VERSION 5.8 ;
BUSBITCHARS "[]" ;
DIVIDERCHAR "/" ;
UNITS
    DATABASE MICRONS 1000 ;
END UNITS

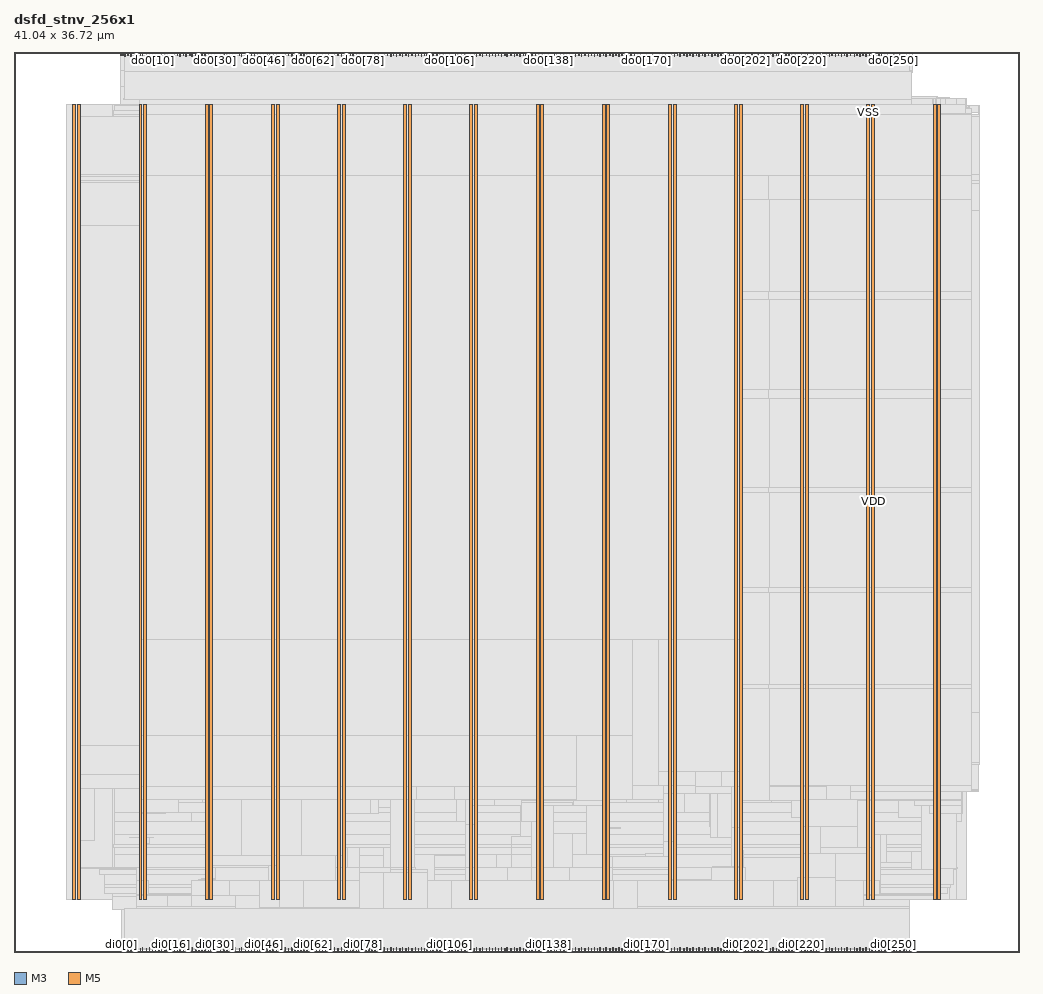
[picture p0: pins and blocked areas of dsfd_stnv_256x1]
MACRO dsfd_stnv_256x1
  FOREIGN dsfd_stnv_256x1 0 0 ;
  CLASS BLOCK ;
  SIZE 41.04 BY 36.72 ;
  PIN di0[0]
    DIRECTION INPUT ;
    USE SIGNAL ;
    PORT
      LAYER M3 ;
        RECT  4.392 0 4.41 0.144 ;
    END
  END di0[0]
  PIN di0[100]
    DIRECTION INPUT ;
    USE SIGNAL ;
    PORT
      LAYER M3 ;
        RECT  16.992 0 17.01 0.144 ;
    END
  END di0[100]
  PIN di0[101]
    DIRECTION INPUT ;
    USE SIGNAL ;
    PORT
      LAYER M5 ;
        RECT  17.088 0 17.112 0.192 ;
    END
  END di0[101]
  PIN di0[102]
    DIRECTION INPUT ;
    USE SIGNAL ;
    PORT
      LAYER M3 ;
        RECT  17.244 0 17.262 0.144 ;
    END
  END di0[102]
  PIN di0[103]
    DIRECTION INPUT ;
    USE SIGNAL ;
    PORT
      LAYER M5 ;
        RECT  17.376 0 17.4 0.192 ;
    END
  END di0[103]
  PIN di0[104]
    DIRECTION INPUT ;
    USE SIGNAL ;
    PORT
      LAYER M3 ;
        RECT  17.496 0 17.514 0.144 ;
    END
  END di0[104]
  PIN di0[105]
    DIRECTION INPUT ;
    USE SIGNAL ;
    PORT
      LAYER M5 ;
        RECT  17.616 0 17.64 0.192 ;
    END
  END di0[105]
  PIN di0[106]
    DIRECTION INPUT ;
    USE SIGNAL ;
    PORT
      LAYER M3 ;
        RECT  17.748 0 17.766 0.144 ;
    END
  END di0[106]
  PIN di0[107]
    DIRECTION INPUT ;
    USE SIGNAL ;
    PORT
      LAYER M5 ;
        RECT  17.856 0 17.88 0.192 ;
    END
  END di0[107]
  PIN di0[108]
    DIRECTION INPUT ;
    USE SIGNAL ;
    PORT
      LAYER M3 ;
        RECT  18 0 18.018 0.144 ;
    END
  END di0[108]
  PIN di0[109]
    DIRECTION INPUT ;
    USE SIGNAL ;
    PORT
      LAYER M5 ;
        RECT  18.096 0 18.12 0.192 ;
    END
  END di0[109]
  PIN di0[10]
    DIRECTION INPUT ;
    USE SIGNAL ;
    PORT
      LAYER M3 ;
        RECT  5.652 0 5.67 0.144 ;
    END
  END di0[10]
  PIN di0[110]
    DIRECTION INPUT ;
    USE SIGNAL ;
    PORT
      LAYER M3 ;
        RECT  18.252 0 18.27 0.144 ;
    END
  END di0[110]
  PIN di0[111]
    DIRECTION INPUT ;
    USE SIGNAL ;
    PORT
      LAYER M5 ;
        RECT  18.384 0 18.408 0.192 ;
    END
  END di0[111]
  PIN di0[112]
    DIRECTION INPUT ;
    USE SIGNAL ;
    PORT
      LAYER M3 ;
        RECT  18.504 0 18.522 0.144 ;
    END
  END di0[112]
  PIN di0[113]
    DIRECTION INPUT ;
    USE SIGNAL ;
    PORT
      LAYER M5 ;
        RECT  18.624 0 18.648 0.192 ;
    END
  END di0[113]
  PIN di0[114]
    DIRECTION INPUT ;
    USE SIGNAL ;
    PORT
      LAYER M3 ;
        RECT  18.756 0 18.774 0.144 ;
    END
  END di0[114]
  PIN di0[115]
    DIRECTION INPUT ;
    USE SIGNAL ;
    PORT
      LAYER M5 ;
        RECT  18.864 0 18.888 0.192 ;
    END
  END di0[115]
  PIN di0[116]
    DIRECTION INPUT ;
    USE SIGNAL ;
    PORT
      LAYER M3 ;
        RECT  19.008 0 19.026 0.144 ;
    END
  END di0[116]
  PIN di0[117]
    DIRECTION INPUT ;
    USE SIGNAL ;
    PORT
      LAYER M5 ;
        RECT  19.104 0 19.128 0.192 ;
    END
  END di0[117]
  PIN di0[118]
    DIRECTION INPUT ;
    USE SIGNAL ;
    PORT
      LAYER M3 ;
        RECT  19.26 0 19.278 0.144 ;
    END
  END di0[118]
  PIN di0[119]
    DIRECTION INPUT ;
    USE SIGNAL ;
    PORT
      LAYER M5 ;
        RECT  19.392 0 19.416 0.192 ;
    END
  END di0[119]
  PIN di0[11]
    DIRECTION INPUT ;
    USE SIGNAL ;
    PORT
      LAYER M5 ;
        RECT  5.76 0 5.784 0.192 ;
    END
  END di0[11]
  PIN di0[120]
    DIRECTION INPUT ;
    USE SIGNAL ;
    PORT
      LAYER M3 ;
        RECT  19.512 0 19.53 0.144 ;
    END
  END di0[120]
  PIN di0[121]
    DIRECTION INPUT ;
    USE SIGNAL ;
    PORT
      LAYER M5 ;
        RECT  19.632 0 19.656 0.192 ;
    END
  END di0[121]
  PIN di0[122]
    DIRECTION INPUT ;
    USE SIGNAL ;
    PORT
      LAYER M3 ;
        RECT  19.764 0 19.782 0.144 ;
    END
  END di0[122]
  PIN di0[123]
    DIRECTION INPUT ;
    USE SIGNAL ;
    PORT
      LAYER M5 ;
        RECT  19.872 0 19.896 0.192 ;
    END
  END di0[123]
  PIN di0[124]
    DIRECTION INPUT ;
    USE SIGNAL ;
    PORT
      LAYER M3 ;
        RECT  20.016 0 20.034 0.144 ;
    END
  END di0[124]
  PIN di0[125]
    DIRECTION INPUT ;
    USE SIGNAL ;
    PORT
      LAYER M5 ;
        RECT  20.112 0 20.136 0.192 ;
    END
  END di0[125]
  PIN di0[126]
    DIRECTION INPUT ;
    USE SIGNAL ;
    PORT
      LAYER M3 ;
        RECT  20.268 0 20.286 0.144 ;
    END
  END di0[126]
  PIN di0[127]
    DIRECTION INPUT ;
    USE SIGNAL ;
    PORT
      LAYER M5 ;
        RECT  20.4 0 20.424 0.192 ;
    END
  END di0[127]
  PIN di0[128]
    DIRECTION INPUT ;
    USE SIGNAL ;
    PORT
      LAYER M3 ;
        RECT  20.52 0 20.538 0.144 ;
    END
  END di0[128]
  PIN di0[129]
    DIRECTION INPUT ;
    USE SIGNAL ;
    PORT
      LAYER M5 ;
        RECT  20.64 0 20.664 0.192 ;
    END
  END di0[129]
  PIN di0[12]
    DIRECTION INPUT ;
    USE SIGNAL ;
    PORT
      LAYER M3 ;
        RECT  5.904 0 5.922 0.144 ;
    END
  END di0[12]
  PIN di0[130]
    DIRECTION INPUT ;
    USE SIGNAL ;
    PORT
      LAYER M3 ;
        RECT  20.772 0 20.79 0.144 ;
    END
  END di0[130]
  PIN di0[131]
    DIRECTION INPUT ;
    USE SIGNAL ;
    PORT
      LAYER M5 ;
        RECT  20.88 0 20.904 0.192 ;
    END
  END di0[131]
  PIN di0[132]
    DIRECTION INPUT ;
    USE SIGNAL ;
    PORT
      LAYER M3 ;
        RECT  21.024 0 21.042 0.144 ;
    END
  END di0[132]
  PIN di0[133]
    DIRECTION INPUT ;
    USE SIGNAL ;
    PORT
      LAYER M5 ;
        RECT  21.12 0 21.144 0.192 ;
    END
  END di0[133]
  PIN di0[134]
    DIRECTION INPUT ;
    USE SIGNAL ;
    PORT
      LAYER M3 ;
        RECT  21.276 0 21.294 0.144 ;
    END
  END di0[134]
  PIN di0[135]
    DIRECTION INPUT ;
    USE SIGNAL ;
    PORT
      LAYER M5 ;
        RECT  21.408 0 21.432 0.192 ;
    END
  END di0[135]
  PIN di0[136]
    DIRECTION INPUT ;
    USE SIGNAL ;
    PORT
      LAYER M3 ;
        RECT  21.528 0 21.546 0.144 ;
    END
  END di0[136]
  PIN di0[137]
    DIRECTION INPUT ;
    USE SIGNAL ;
    PORT
      LAYER M5 ;
        RECT  21.648 0 21.672 0.192 ;
    END
  END di0[137]
  PIN di0[138]
    DIRECTION INPUT ;
    USE SIGNAL ;
    PORT
      LAYER M3 ;
        RECT  21.78 0 21.798 0.144 ;
    END
  END di0[138]
  PIN di0[139]
    DIRECTION INPUT ;
    USE SIGNAL ;
    PORT
      LAYER M5 ;
        RECT  21.888 0 21.912 0.192 ;
    END
  END di0[139]
  PIN di0[13]
    DIRECTION INPUT ;
    USE SIGNAL ;
    PORT
      LAYER M5 ;
        RECT  6 0 6.024 0.192 ;
    END
  END di0[13]
  PIN di0[140]
    DIRECTION INPUT ;
    USE SIGNAL ;
    PORT
      LAYER M3 ;
        RECT  22.032 0 22.05 0.144 ;
    END
  END di0[140]
  PIN di0[141]
    DIRECTION INPUT ;
    USE SIGNAL ;
    PORT
      LAYER M5 ;
        RECT  22.128 0 22.152 0.192 ;
    END
  END di0[141]
  PIN di0[142]
    DIRECTION INPUT ;
    USE SIGNAL ;
    PORT
      LAYER M3 ;
        RECT  22.284 0 22.302 0.144 ;
    END
  END di0[142]
  PIN di0[143]
    DIRECTION INPUT ;
    USE SIGNAL ;
    PORT
      LAYER M5 ;
        RECT  22.416 0 22.44 0.192 ;
    END
  END di0[143]
  PIN di0[144]
    DIRECTION INPUT ;
    USE SIGNAL ;
    PORT
      LAYER M3 ;
        RECT  22.536 0 22.554 0.144 ;
    END
  END di0[144]
  PIN di0[145]
    DIRECTION INPUT ;
    USE SIGNAL ;
    PORT
      LAYER M5 ;
        RECT  22.656 0 22.68 0.192 ;
    END
  END di0[145]
  PIN di0[146]
    DIRECTION INPUT ;
    USE SIGNAL ;
    PORT
      LAYER M3 ;
        RECT  22.788 0 22.806 0.144 ;
    END
  END di0[146]
  PIN di0[147]
    DIRECTION INPUT ;
    USE SIGNAL ;
    PORT
      LAYER M5 ;
        RECT  22.896 0 22.92 0.192 ;
    END
  END di0[147]
  PIN di0[148]
    DIRECTION INPUT ;
    USE SIGNAL ;
    PORT
      LAYER M3 ;
        RECT  23.04 0 23.058 0.144 ;
    END
  END di0[148]
  PIN di0[149]
    DIRECTION INPUT ;
    USE SIGNAL ;
    PORT
      LAYER M5 ;
        RECT  23.136 0 23.16 0.192 ;
    END
  END di0[149]
  PIN di0[14]
    DIRECTION INPUT ;
    USE SIGNAL ;
    PORT
      LAYER M3 ;
        RECT  6.156 0 6.174 0.144 ;
    END
  END di0[14]
  PIN di0[150]
    DIRECTION INPUT ;
    USE SIGNAL ;
    PORT
      LAYER M3 ;
        RECT  23.292 0 23.31 0.144 ;
    END
  END di0[150]
  PIN di0[151]
    DIRECTION INPUT ;
    USE SIGNAL ;
    PORT
      LAYER M5 ;
        RECT  23.424 0 23.448 0.192 ;
    END
  END di0[151]
  PIN di0[152]
    DIRECTION INPUT ;
    USE SIGNAL ;
    PORT
      LAYER M3 ;
        RECT  23.544 0 23.562 0.144 ;
    END
  END di0[152]
  PIN di0[153]
    DIRECTION INPUT ;
    USE SIGNAL ;
    PORT
      LAYER M5 ;
        RECT  23.664 0 23.688 0.192 ;
    END
  END di0[153]
  PIN di0[154]
    DIRECTION INPUT ;
    USE SIGNAL ;
    PORT
      LAYER M3 ;
        RECT  23.796 0 23.814 0.144 ;
    END
  END di0[154]
  PIN di0[155]
    DIRECTION INPUT ;
    USE SIGNAL ;
    PORT
      LAYER M5 ;
        RECT  23.904 0 23.928 0.192 ;
    END
  END di0[155]
  PIN di0[156]
    DIRECTION INPUT ;
    USE SIGNAL ;
    PORT
      LAYER M3 ;
        RECT  24.048 0 24.066 0.144 ;
    END
  END di0[156]
  PIN di0[157]
    DIRECTION INPUT ;
    USE SIGNAL ;
    PORT
      LAYER M5 ;
        RECT  24.144 0 24.168 0.192 ;
    END
  END di0[157]
  PIN di0[158]
    DIRECTION INPUT ;
    USE SIGNAL ;
    PORT
      LAYER M3 ;
        RECT  24.3 0 24.318 0.144 ;
    END
  END di0[158]
  PIN di0[159]
    DIRECTION INPUT ;
    USE SIGNAL ;
    PORT
      LAYER M5 ;
        RECT  24.432 0 24.456 0.192 ;
    END
  END di0[159]
  PIN di0[15]
    DIRECTION INPUT ;
    USE SIGNAL ;
    PORT
      LAYER M5 ;
        RECT  6.24 0 6.264 0.192 ;
    END
  END di0[15]
  PIN di0[160]
    DIRECTION INPUT ;
    USE SIGNAL ;
    PORT
      LAYER M3 ;
        RECT  24.552 0 24.57 0.144 ;
    END
  END di0[160]
  PIN di0[161]
    DIRECTION INPUT ;
    USE SIGNAL ;
    PORT
      LAYER M5 ;
        RECT  24.672 0 24.696 0.192 ;
    END
  END di0[161]
  PIN di0[162]
    DIRECTION INPUT ;
    USE SIGNAL ;
    PORT
      LAYER M3 ;
        RECT  24.804 0 24.822 0.144 ;
    END
  END di0[162]
  PIN di0[163]
    DIRECTION INPUT ;
    USE SIGNAL ;
    PORT
      LAYER M5 ;
        RECT  24.912 0 24.936 0.192 ;
    END
  END di0[163]
  PIN di0[164]
    DIRECTION INPUT ;
    USE SIGNAL ;
    PORT
      LAYER M3 ;
        RECT  25.056 0 25.074 0.144 ;
    END
  END di0[164]
  PIN di0[165]
    DIRECTION INPUT ;
    USE SIGNAL ;
    PORT
      LAYER M5 ;
        RECT  25.152 0 25.176 0.192 ;
    END
  END di0[165]
  PIN di0[166]
    DIRECTION INPUT ;
    USE SIGNAL ;
    PORT
      LAYER M3 ;
        RECT  25.308 0 25.326 0.144 ;
    END
  END di0[166]
  PIN di0[167]
    DIRECTION INPUT ;
    USE SIGNAL ;
    PORT
      LAYER M5 ;
        RECT  25.44 0 25.464 0.192 ;
    END
  END di0[167]
  PIN di0[168]
    DIRECTION INPUT ;
    USE SIGNAL ;
    PORT
      LAYER M3 ;
        RECT  25.56 0 25.578 0.144 ;
    END
  END di0[168]
  PIN di0[169]
    DIRECTION INPUT ;
    USE SIGNAL ;
    PORT
      LAYER M5 ;
        RECT  25.68 0 25.704 0.192 ;
    END
  END di0[169]
  PIN di0[16]
    DIRECTION INPUT ;
    USE SIGNAL ;
    PORT
      LAYER M3 ;
        RECT  6.408 0 6.426 0.144 ;
    END
  END di0[16]
  PIN di0[170]
    DIRECTION INPUT ;
    USE SIGNAL ;
    PORT
      LAYER M3 ;
        RECT  25.812 0 25.83 0.144 ;
    END
  END di0[170]
  PIN di0[171]
    DIRECTION INPUT ;
    USE SIGNAL ;
    PORT
      LAYER M5 ;
        RECT  25.92 0 25.944 0.192 ;
    END
  END di0[171]
  PIN di0[172]
    DIRECTION INPUT ;
    USE SIGNAL ;
    PORT
      LAYER M3 ;
        RECT  26.064 0 26.082 0.144 ;
    END
  END di0[172]
  PIN di0[173]
    DIRECTION INPUT ;
    USE SIGNAL ;
    PORT
      LAYER M5 ;
        RECT  26.16 0 26.184 0.192 ;
    END
  END di0[173]
  PIN di0[174]
    DIRECTION INPUT ;
    USE SIGNAL ;
    PORT
      LAYER M3 ;
        RECT  26.316 0 26.334 0.144 ;
    END
  END di0[174]
  PIN di0[175]
    DIRECTION INPUT ;
    USE SIGNAL ;
    PORT
      LAYER M5 ;
        RECT  26.448 0 26.472 0.192 ;
    END
  END di0[175]
  PIN di0[176]
    DIRECTION INPUT ;
    USE SIGNAL ;
    PORT
      LAYER M3 ;
        RECT  26.568 0 26.586 0.144 ;
    END
  END di0[176]
  PIN di0[177]
    DIRECTION INPUT ;
    USE SIGNAL ;
    PORT
      LAYER M5 ;
        RECT  26.688 0 26.712 0.192 ;
    END
  END di0[177]
  PIN di0[178]
    DIRECTION INPUT ;
    USE SIGNAL ;
    PORT
      LAYER M3 ;
        RECT  26.82 0 26.838 0.144 ;
    END
  END di0[178]
  PIN di0[179]
    DIRECTION INPUT ;
    USE SIGNAL ;
    PORT
      LAYER M5 ;
        RECT  26.928 0 26.952 0.192 ;
    END
  END di0[179]
  PIN di0[17]
    DIRECTION INPUT ;
    USE SIGNAL ;
    PORT
      LAYER M5 ;
        RECT  6.528 0 6.552 0.192 ;
    END
  END di0[17]
  PIN di0[180]
    DIRECTION INPUT ;
    USE SIGNAL ;
    PORT
      LAYER M3 ;
        RECT  27.072 0 27.09 0.144 ;
    END
  END di0[180]
  PIN di0[181]
    DIRECTION INPUT ;
    USE SIGNAL ;
    PORT
      LAYER M5 ;
        RECT  27.168 0 27.192 0.192 ;
    END
  END di0[181]
  PIN di0[182]
    DIRECTION INPUT ;
    USE SIGNAL ;
    PORT
      LAYER M3 ;
        RECT  27.324 0 27.342 0.144 ;
    END
  END di0[182]
  PIN di0[183]
    DIRECTION INPUT ;
    USE SIGNAL ;
    PORT
      LAYER M5 ;
        RECT  27.456 0 27.48 0.192 ;
    END
  END di0[183]
  PIN di0[184]
    DIRECTION INPUT ;
    USE SIGNAL ;
    PORT
      LAYER M3 ;
        RECT  27.576 0 27.594 0.144 ;
    END
  END di0[184]
  PIN di0[185]
    DIRECTION INPUT ;
    USE SIGNAL ;
    PORT
      LAYER M5 ;
        RECT  27.696 0 27.72 0.192 ;
    END
  END di0[185]
  PIN di0[186]
    DIRECTION INPUT ;
    USE SIGNAL ;
    PORT
      LAYER M3 ;
        RECT  27.828 0 27.846 0.144 ;
    END
  END di0[186]
  PIN di0[187]
    DIRECTION INPUT ;
    USE SIGNAL ;
    PORT
      LAYER M5 ;
        RECT  27.936 0 27.96 0.192 ;
    END
  END di0[187]
  PIN di0[188]
    DIRECTION INPUT ;
    USE SIGNAL ;
    PORT
      LAYER M3 ;
        RECT  28.08 0 28.098 0.144 ;
    END
  END di0[188]
  PIN di0[189]
    DIRECTION INPUT ;
    USE SIGNAL ;
    PORT
      LAYER M5 ;
        RECT  28.176 0 28.2 0.192 ;
    END
  END di0[189]
  PIN di0[18]
    DIRECTION INPUT ;
    USE SIGNAL ;
    PORT
      LAYER M3 ;
        RECT  6.66 0 6.678 0.144 ;
    END
  END di0[18]
  PIN di0[190]
    DIRECTION INPUT ;
    USE SIGNAL ;
    PORT
      LAYER M3 ;
        RECT  28.332 0 28.35 0.144 ;
    END
  END di0[190]
  PIN di0[191]
    DIRECTION INPUT ;
    USE SIGNAL ;
    PORT
      LAYER M5 ;
        RECT  28.464 0 28.488 0.192 ;
    END
  END di0[191]
  PIN di0[192]
    DIRECTION INPUT ;
    USE SIGNAL ;
    PORT
      LAYER M3 ;
        RECT  28.584 0 28.602 0.144 ;
    END
  END di0[192]
  PIN di0[193]
    DIRECTION INPUT ;
    USE SIGNAL ;
    PORT
      LAYER M5 ;
        RECT  28.704 0 28.728 0.192 ;
    END
  END di0[193]
  PIN di0[194]
    DIRECTION INPUT ;
    USE SIGNAL ;
    PORT
      LAYER M3 ;
        RECT  28.836 0 28.854 0.144 ;
    END
  END di0[194]
  PIN di0[195]
    DIRECTION INPUT ;
    USE SIGNAL ;
    PORT
      LAYER M5 ;
        RECT  28.944 0 28.968 0.192 ;
    END
  END di0[195]
  PIN di0[196]
    DIRECTION INPUT ;
    USE SIGNAL ;
    PORT
      LAYER M3 ;
        RECT  29.088 0 29.106 0.144 ;
    END
  END di0[196]
  PIN di0[197]
    DIRECTION INPUT ;
    USE SIGNAL ;
    PORT
      LAYER M5 ;
        RECT  29.184 0 29.208 0.192 ;
    END
  END di0[197]
  PIN di0[198]
    DIRECTION INPUT ;
    USE SIGNAL ;
    PORT
      LAYER M3 ;
        RECT  29.34 0 29.358 0.144 ;
    END
  END di0[198]
  PIN di0[199]
    DIRECTION INPUT ;
    USE SIGNAL ;
    PORT
      LAYER M5 ;
        RECT  29.472 0 29.496 0.192 ;
    END
  END di0[199]
  PIN di0[19]
    DIRECTION INPUT ;
    USE SIGNAL ;
    PORT
      LAYER M5 ;
        RECT  6.768 0 6.792 0.192 ;
    END
  END di0[19]
  PIN di0[1]
    DIRECTION INPUT ;
    USE SIGNAL ;
    PORT
      LAYER M5 ;
        RECT  4.512 0 4.536 0.192 ;
    END
  END di0[1]
  PIN di0[200]
    DIRECTION INPUT ;
    USE SIGNAL ;
    PORT
      LAYER M3 ;
        RECT  29.592 0 29.61 0.144 ;
    END
  END di0[200]
  PIN di0[201]
    DIRECTION INPUT ;
    USE SIGNAL ;
    PORT
      LAYER M5 ;
        RECT  29.712 0 29.736 0.192 ;
    END
  END di0[201]
  PIN di0[202]
    DIRECTION INPUT ;
    USE SIGNAL ;
    PORT
      LAYER M3 ;
        RECT  29.844 0 29.862 0.144 ;
    END
  END di0[202]
  PIN di0[203]
    DIRECTION INPUT ;
    USE SIGNAL ;
    PORT
      LAYER M5 ;
        RECT  29.952 0 29.976 0.192 ;
    END
  END di0[203]
  PIN di0[204]
    DIRECTION INPUT ;
    USE SIGNAL ;
    PORT
      LAYER M3 ;
        RECT  30.096 0 30.114 0.144 ;
    END
  END di0[204]
  PIN di0[205]
    DIRECTION INPUT ;
    USE SIGNAL ;
    PORT
      LAYER M5 ;
        RECT  30.192 0 30.216 0.192 ;
    END
  END di0[205]
  PIN di0[206]
    DIRECTION INPUT ;
    USE SIGNAL ;
    PORT
      LAYER M3 ;
        RECT  30.348 0 30.366 0.144 ;
    END
  END di0[206]
  PIN di0[207]
    DIRECTION INPUT ;
    USE SIGNAL ;
    PORT
      LAYER M5 ;
        RECT  30.48 0 30.504 0.192 ;
    END
  END di0[207]
  PIN di0[208]
    DIRECTION INPUT ;
    USE SIGNAL ;
    PORT
      LAYER M3 ;
        RECT  30.6 0 30.618 0.144 ;
    END
  END di0[208]
  PIN di0[209]
    DIRECTION INPUT ;
    USE SIGNAL ;
    PORT
      LAYER M5 ;
        RECT  30.72 0 30.744 0.192 ;
    END
  END di0[209]
  PIN di0[20]
    DIRECTION INPUT ;
    USE SIGNAL ;
    PORT
      LAYER M3 ;
        RECT  6.912 0 6.93 0.144 ;
    END
  END di0[20]
  PIN di0[210]
    DIRECTION INPUT ;
    USE SIGNAL ;
    PORT
      LAYER M3 ;
        RECT  30.852 0 30.87 0.144 ;
    END
  END di0[210]
  PIN di0[211]
    DIRECTION INPUT ;
    USE SIGNAL ;
    PORT
      LAYER M5 ;
        RECT  30.96 0 30.984 0.192 ;
    END
  END di0[211]
  PIN di0[212]
    DIRECTION INPUT ;
    USE SIGNAL ;
    PORT
      LAYER M3 ;
        RECT  31.104 0 31.122 0.144 ;
    END
  END di0[212]
  PIN di0[213]
    DIRECTION INPUT ;
    USE SIGNAL ;
    PORT
      LAYER M5 ;
        RECT  31.2 0 31.224 0.192 ;
    END
  END di0[213]
  PIN di0[214]
    DIRECTION INPUT ;
    USE SIGNAL ;
    PORT
      LAYER M3 ;
        RECT  31.356 0 31.374 0.144 ;
    END
  END di0[214]
  PIN di0[215]
    DIRECTION INPUT ;
    USE SIGNAL ;
    PORT
      LAYER M5 ;
        RECT  31.488 0 31.512 0.192 ;
    END
  END di0[215]
  PIN di0[216]
    DIRECTION INPUT ;
    USE SIGNAL ;
    PORT
      LAYER M3 ;
        RECT  31.608 0 31.626 0.144 ;
    END
  END di0[216]
  PIN di0[217]
    DIRECTION INPUT ;
    USE SIGNAL ;
    PORT
      LAYER M5 ;
        RECT  31.728 0 31.752 0.192 ;
    END
  END di0[217]
  PIN di0[218]
    DIRECTION INPUT ;
    USE SIGNAL ;
    PORT
      LAYER M3 ;
        RECT  31.86 0 31.878 0.144 ;
    END
  END di0[218]
  PIN di0[219]
    DIRECTION INPUT ;
    USE SIGNAL ;
    PORT
      LAYER M5 ;
        RECT  31.968 0 31.992 0.192 ;
    END
  END di0[219]
  PIN di0[21]
    DIRECTION INPUT ;
    USE SIGNAL ;
    PORT
      LAYER M5 ;
        RECT  7.008 0 7.032 0.192 ;
    END
  END di0[21]
  PIN di0[220]
    DIRECTION INPUT ;
    USE SIGNAL ;
    PORT
      LAYER M3 ;
        RECT  32.112 0 32.13 0.144 ;
    END
  END di0[220]
  PIN di0[221]
    DIRECTION INPUT ;
    USE SIGNAL ;
    PORT
      LAYER M5 ;
        RECT  32.256 0 32.28 0.192 ;
    END
  END di0[221]
  PIN di0[222]
    DIRECTION INPUT ;
    USE SIGNAL ;
    PORT
      LAYER M3 ;
        RECT  32.364 0 32.382 0.144 ;
    END
  END di0[222]
  PIN di0[223]
    DIRECTION INPUT ;
    USE SIGNAL ;
    PORT
      LAYER M5 ;
        RECT  32.496 0 32.52 0.192 ;
    END
  END di0[223]
  PIN di0[224]
    DIRECTION INPUT ;
    USE SIGNAL ;
    PORT
      LAYER M3 ;
        RECT  32.616 0 32.634 0.144 ;
    END
  END di0[224]
  PIN di0[225]
    DIRECTION INPUT ;
    USE SIGNAL ;
    PORT
      LAYER M5 ;
        RECT  32.736 0 32.76 0.192 ;
    END
  END di0[225]
  PIN di0[226]
    DIRECTION INPUT ;
    USE SIGNAL ;
    PORT
      LAYER M3 ;
        RECT  32.868 0 32.886 0.144 ;
    END
  END di0[226]
  PIN di0[227]
    DIRECTION INPUT ;
    USE SIGNAL ;
    PORT
      LAYER M5 ;
        RECT  32.976 0 33 0.192 ;
    END
  END di0[227]
  PIN di0[228]
    DIRECTION INPUT ;
    USE SIGNAL ;
    PORT
      LAYER M3 ;
        RECT  33.12 0 33.138 0.144 ;
    END
  END di0[228]
  PIN di0[229]
    DIRECTION INPUT ;
    USE SIGNAL ;
    PORT
      LAYER M5 ;
        RECT  33.264 0 33.288 0.192 ;
    END
  END di0[229]
  PIN di0[22]
    DIRECTION INPUT ;
    USE SIGNAL ;
    PORT
      LAYER M3 ;
        RECT  7.164 0 7.182 0.144 ;
    END
  END di0[22]
  PIN di0[230]
    DIRECTION INPUT ;
    USE SIGNAL ;
    PORT
      LAYER M3 ;
        RECT  33.372 0 33.39 0.144 ;
    END
  END di0[230]
  PIN di0[231]
    DIRECTION INPUT ;
    USE SIGNAL ;
    PORT
      LAYER M5 ;
        RECT  33.504 0 33.528 0.192 ;
    END
  END di0[231]
  PIN di0[232]
    DIRECTION INPUT ;
    USE SIGNAL ;
    PORT
      LAYER M3 ;
        RECT  33.624 0 33.642 0.144 ;
    END
  END di0[232]
  PIN di0[233]
    DIRECTION INPUT ;
    USE SIGNAL ;
    PORT
      LAYER M5 ;
        RECT  33.744 0 33.768 0.192 ;
    END
  END di0[233]
  PIN di0[234]
    DIRECTION INPUT ;
    USE SIGNAL ;
    PORT
      LAYER M3 ;
        RECT  33.876 0 33.894 0.144 ;
    END
  END di0[234]
  PIN di0[235]
    DIRECTION INPUT ;
    USE SIGNAL ;
    PORT
      LAYER M5 ;
        RECT  33.984 0 34.008 0.192 ;
    END
  END di0[235]
  PIN di0[236]
    DIRECTION INPUT ;
    USE SIGNAL ;
    PORT
      LAYER M3 ;
        RECT  34.128 0 34.146 0.144 ;
    END
  END di0[236]
  PIN di0[237]
    DIRECTION INPUT ;
    USE SIGNAL ;
    PORT
      LAYER M5 ;
        RECT  34.272 0 34.296 0.192 ;
    END
  END di0[237]
  PIN di0[238]
    DIRECTION INPUT ;
    USE SIGNAL ;
    PORT
      LAYER M3 ;
        RECT  34.38 0 34.398 0.144 ;
    END
  END di0[238]
  PIN di0[239]
    DIRECTION INPUT ;
    USE SIGNAL ;
    PORT
      LAYER M5 ;
        RECT  34.512 0 34.536 0.192 ;
    END
  END di0[239]
  PIN di0[23]
    DIRECTION INPUT ;
    USE SIGNAL ;
    PORT
      LAYER M5 ;
        RECT  7.248 0 7.272 0.192 ;
    END
  END di0[23]
  PIN di0[240]
    DIRECTION INPUT ;
    USE SIGNAL ;
    PORT
      LAYER M3 ;
        RECT  34.632 0 34.65 0.144 ;
    END
  END di0[240]
  PIN di0[241]
    DIRECTION INPUT ;
    USE SIGNAL ;
    PORT
      LAYER M5 ;
        RECT  34.752 0 34.776 0.192 ;
    END
  END di0[241]
  PIN di0[242]
    DIRECTION INPUT ;
    USE SIGNAL ;
    PORT
      LAYER M3 ;
        RECT  34.884 0 34.902 0.144 ;
    END
  END di0[242]
  PIN di0[243]
    DIRECTION INPUT ;
    USE SIGNAL ;
    PORT
      LAYER M5 ;
        RECT  34.992 0 35.016 0.192 ;
    END
  END di0[243]
  PIN di0[244]
    DIRECTION INPUT ;
    USE SIGNAL ;
    PORT
      LAYER M3 ;
        RECT  35.136 0 35.154 0.144 ;
    END
  END di0[244]
  PIN di0[245]
    DIRECTION INPUT ;
    USE SIGNAL ;
    PORT
      LAYER M5 ;
        RECT  35.28 0 35.304 0.192 ;
    END
  END di0[245]
  PIN di0[246]
    DIRECTION INPUT ;
    USE SIGNAL ;
    PORT
      LAYER M3 ;
        RECT  35.388 0 35.406 0.144 ;
    END
  END di0[246]
  PIN di0[247]
    DIRECTION INPUT ;
    USE SIGNAL ;
    PORT
      LAYER M5 ;
        RECT  35.52 0 35.544 0.192 ;
    END
  END di0[247]
  PIN di0[248]
    DIRECTION INPUT ;
    USE SIGNAL ;
    PORT
      LAYER M3 ;
        RECT  35.64 0 35.658 0.144 ;
    END
  END di0[248]
  PIN di0[249]
    DIRECTION INPUT ;
    USE SIGNAL ;
    PORT
      LAYER M5 ;
        RECT  35.76 0 35.784 0.192 ;
    END
  END di0[249]
  PIN di0[24]
    DIRECTION INPUT ;
    USE SIGNAL ;
    PORT
      LAYER M3 ;
        RECT  7.416 0 7.434 0.144 ;
    END
  END di0[24]
  PIN di0[250]
    DIRECTION INPUT ;
    USE SIGNAL ;
    PORT
      LAYER M3 ;
        RECT  35.892 0 35.91 0.144 ;
    END
  END di0[250]
  PIN di0[251]
    DIRECTION INPUT ;
    USE SIGNAL ;
    PORT
      LAYER M5 ;
        RECT  36 0 36.024 0.192 ;
    END
  END di0[251]
  PIN di0[252]
    DIRECTION INPUT ;
    USE SIGNAL ;
    PORT
      LAYER M3 ;
        RECT  36.144 0 36.162 0.144 ;
    END
  END di0[252]
  PIN di0[253]
    DIRECTION INPUT ;
    USE SIGNAL ;
    PORT
      LAYER M5 ;
        RECT  36.288 0 36.312 0.192 ;
    END
  END di0[253]
  PIN di0[254]
    DIRECTION INPUT ;
    USE SIGNAL ;
    PORT
      LAYER M3 ;
        RECT  36.396 0 36.414 0.144 ;
    END
  END di0[254]
  PIN di0[255]
    DIRECTION INPUT ;
    USE SIGNAL ;
    PORT
      LAYER M5 ;
        RECT  36.528 0 36.552 0.192 ;
    END
  END di0[255]
  PIN di0[25]
    DIRECTION INPUT ;
    USE SIGNAL ;
    PORT
      LAYER M5 ;
        RECT  7.536 0 7.56 0.192 ;
    END
  END di0[25]
  PIN di0[26]
    DIRECTION INPUT ;
    USE SIGNAL ;
    PORT
      LAYER M3 ;
        RECT  7.668 0 7.686 0.144 ;
    END
  END di0[26]
  PIN di0[27]
    DIRECTION INPUT ;
    USE SIGNAL ;
    PORT
      LAYER M5 ;
        RECT  7.776 0 7.8 0.192 ;
    END
  END di0[27]
  PIN di0[28]
    DIRECTION INPUT ;
    USE SIGNAL ;
    PORT
      LAYER M3 ;
        RECT  7.92 0 7.938 0.144 ;
    END
  END di0[28]
  PIN di0[29]
    DIRECTION INPUT ;
    USE SIGNAL ;
    PORT
      LAYER M5 ;
        RECT  8.016 0 8.04 0.192 ;
    END
  END di0[29]
  PIN di0[2]
    DIRECTION INPUT ;
    USE SIGNAL ;
    PORT
      LAYER M3 ;
        RECT  4.644 0 4.662 0.144 ;
    END
  END di0[2]
  PIN di0[30]
    DIRECTION INPUT ;
    USE SIGNAL ;
    PORT
      LAYER M3 ;
        RECT  8.172 0 8.19 0.144 ;
    END
  END di0[30]
  PIN di0[31]
    DIRECTION INPUT ;
    USE SIGNAL ;
    PORT
      LAYER M5 ;
        RECT  8.256 0 8.28 0.192 ;
    END
  END di0[31]
  PIN di0[32]
    DIRECTION INPUT ;
    USE SIGNAL ;
    PORT
      LAYER M3 ;
        RECT  8.424 0 8.442 0.144 ;
    END
  END di0[32]
  PIN di0[33]
    DIRECTION INPUT ;
    USE SIGNAL ;
    PORT
      LAYER M5 ;
        RECT  8.544 0 8.568 0.192 ;
    END
  END di0[33]
  PIN di0[34]
    DIRECTION INPUT ;
    USE SIGNAL ;
    PORT
      LAYER M3 ;
        RECT  8.676 0 8.694 0.144 ;
    END
  END di0[34]
  PIN di0[35]
    DIRECTION INPUT ;
    USE SIGNAL ;
    PORT
      LAYER M5 ;
        RECT  8.784 0 8.808 0.192 ;
    END
  END di0[35]
  PIN di0[36]
    DIRECTION INPUT ;
    USE SIGNAL ;
    PORT
      LAYER M3 ;
        RECT  8.928 0 8.946 0.144 ;
    END
  END di0[36]
  PIN di0[37]
    DIRECTION INPUT ;
    USE SIGNAL ;
    PORT
      LAYER M5 ;
        RECT  9.024 0 9.048 0.192 ;
    END
  END di0[37]
  PIN di0[38]
    DIRECTION INPUT ;
    USE SIGNAL ;
    PORT
      LAYER M3 ;
        RECT  9.18 0 9.198 0.144 ;
    END
  END di0[38]
  PIN di0[39]
    DIRECTION INPUT ;
    USE SIGNAL ;
    PORT
      LAYER M5 ;
        RECT  9.264 0 9.288 0.192 ;
    END
  END di0[39]
  PIN di0[3]
    DIRECTION INPUT ;
    USE SIGNAL ;
    PORT
      LAYER M5 ;
        RECT  4.752 0 4.776 0.192 ;
    END
  END di0[3]
  PIN di0[40]
    DIRECTION INPUT ;
    USE SIGNAL ;
    PORT
      LAYER M3 ;
        RECT  9.432 0 9.45 0.144 ;
    END
  END di0[40]
  PIN di0[41]
    DIRECTION INPUT ;
    USE SIGNAL ;
    PORT
      LAYER M5 ;
        RECT  9.552 0 9.576 0.192 ;
    END
  END di0[41]
  PIN di0[42]
    DIRECTION INPUT ;
    USE SIGNAL ;
    PORT
      LAYER M3 ;
        RECT  9.684 0 9.702 0.144 ;
    END
  END di0[42]
  PIN di0[43]
    DIRECTION INPUT ;
    USE SIGNAL ;
    PORT
      LAYER M5 ;
        RECT  9.792 0 9.816 0.192 ;
    END
  END di0[43]
  PIN di0[44]
    DIRECTION INPUT ;
    USE SIGNAL ;
    PORT
      LAYER M3 ;
        RECT  9.936 0 9.954 0.144 ;
    END
  END di0[44]
  PIN di0[45]
    DIRECTION INPUT ;
    USE SIGNAL ;
    PORT
      LAYER M5 ;
        RECT  10.032 0 10.056 0.192 ;
    END
  END di0[45]
  PIN di0[46]
    DIRECTION INPUT ;
    USE SIGNAL ;
    PORT
      LAYER M3 ;
        RECT  10.188 0 10.206 0.144 ;
    END
  END di0[46]
  PIN di0[47]
    DIRECTION INPUT ;
    USE SIGNAL ;
    PORT
      LAYER M5 ;
        RECT  10.32 0 10.344 0.192 ;
    END
  END di0[47]
  PIN di0[48]
    DIRECTION INPUT ;
    USE SIGNAL ;
    PORT
      LAYER M3 ;
        RECT  10.44 0 10.458 0.144 ;
    END
  END di0[48]
  PIN di0[49]
    DIRECTION INPUT ;
    USE SIGNAL ;
    PORT
      LAYER M5 ;
        RECT  10.56 0 10.584 0.192 ;
    END
  END di0[49]
  PIN di0[4]
    DIRECTION INPUT ;
    USE SIGNAL ;
    PORT
      LAYER M3 ;
        RECT  4.896 0 4.914 0.144 ;
    END
  END di0[4]
  PIN di0[50]
    DIRECTION INPUT ;
    USE SIGNAL ;
    PORT
      LAYER M3 ;
        RECT  10.692 0 10.71 0.144 ;
    END
  END di0[50]
  PIN di0[51]
    DIRECTION INPUT ;
    USE SIGNAL ;
    PORT
      LAYER M5 ;
        RECT  10.8 0 10.824 0.192 ;
    END
  END di0[51]
  PIN di0[52]
    DIRECTION INPUT ;
    USE SIGNAL ;
    PORT
      LAYER M3 ;
        RECT  10.944 0 10.962 0.144 ;
    END
  END di0[52]
  PIN di0[53]
    DIRECTION INPUT ;
    USE SIGNAL ;
    PORT
      LAYER M5 ;
        RECT  11.04 0 11.064 0.192 ;
    END
  END di0[53]
  PIN di0[54]
    DIRECTION INPUT ;
    USE SIGNAL ;
    PORT
      LAYER M3 ;
        RECT  11.196 0 11.214 0.144 ;
    END
  END di0[54]
  PIN di0[55]
    DIRECTION INPUT ;
    USE SIGNAL ;
    PORT
      LAYER M5 ;
        RECT  11.328 0 11.352 0.192 ;
    END
  END di0[55]
  PIN di0[56]
    DIRECTION INPUT ;
    USE SIGNAL ;
    PORT
      LAYER M3 ;
        RECT  11.448 0 11.466 0.144 ;
    END
  END di0[56]
  PIN di0[57]
    DIRECTION INPUT ;
    USE SIGNAL ;
    PORT
      LAYER M5 ;
        RECT  11.568 0 11.592 0.192 ;
    END
  END di0[57]
  PIN di0[58]
    DIRECTION INPUT ;
    USE SIGNAL ;
    PORT
      LAYER M3 ;
        RECT  11.7 0 11.718 0.144 ;
    END
  END di0[58]
  PIN di0[59]
    DIRECTION INPUT ;
    USE SIGNAL ;
    PORT
      LAYER M5 ;
        RECT  11.808 0 11.832 0.192 ;
    END
  END di0[59]
  PIN di0[5]
    DIRECTION INPUT ;
    USE SIGNAL ;
    PORT
      LAYER M5 ;
        RECT  4.992 0 5.016 0.192 ;
    END
  END di0[5]
  PIN di0[60]
    DIRECTION INPUT ;
    USE SIGNAL ;
    PORT
      LAYER M3 ;
        RECT  11.952 0 11.97 0.144 ;
    END
  END di0[60]
  PIN di0[61]
    DIRECTION INPUT ;
    USE SIGNAL ;
    PORT
      LAYER M5 ;
        RECT  12.048 0 12.072 0.192 ;
    END
  END di0[61]
  PIN di0[62]
    DIRECTION INPUT ;
    USE SIGNAL ;
    PORT
      LAYER M3 ;
        RECT  12.204 0 12.222 0.144 ;
    END
  END di0[62]
  PIN di0[63]
    DIRECTION INPUT ;
    USE SIGNAL ;
    PORT
      LAYER M5 ;
        RECT  12.336 0 12.36 0.192 ;
    END
  END di0[63]
  PIN di0[64]
    DIRECTION INPUT ;
    USE SIGNAL ;
    PORT
      LAYER M3 ;
        RECT  12.456 0 12.474 0.144 ;
    END
  END di0[64]
  PIN di0[65]
    DIRECTION INPUT ;
    USE SIGNAL ;
    PORT
      LAYER M5 ;
        RECT  12.576 0 12.6 0.192 ;
    END
  END di0[65]
  PIN di0[66]
    DIRECTION INPUT ;
    USE SIGNAL ;
    PORT
      LAYER M3 ;
        RECT  12.708 0 12.726 0.144 ;
    END
  END di0[66]
  PIN di0[67]
    DIRECTION INPUT ;
    USE SIGNAL ;
    PORT
      LAYER M5 ;
        RECT  12.816 0 12.84 0.192 ;
    END
  END di0[67]
  PIN di0[68]
    DIRECTION INPUT ;
    USE SIGNAL ;
    PORT
      LAYER M3 ;
        RECT  12.96 0 12.978 0.144 ;
    END
  END di0[68]
  PIN di0[69]
    DIRECTION INPUT ;
    USE SIGNAL ;
    PORT
      LAYER M5 ;
        RECT  13.056 0 13.08 0.192 ;
    END
  END di0[69]
  PIN di0[6]
    DIRECTION INPUT ;
    USE SIGNAL ;
    PORT
      LAYER M3 ;
        RECT  5.148 0 5.166 0.144 ;
    END
  END di0[6]
  PIN di0[70]
    DIRECTION INPUT ;
    USE SIGNAL ;
    PORT
      LAYER M3 ;
        RECT  13.212 0 13.23 0.144 ;
    END
  END di0[70]
  PIN di0[71]
    DIRECTION INPUT ;
    USE SIGNAL ;
    PORT
      LAYER M5 ;
        RECT  13.344 0 13.368 0.192 ;
    END
  END di0[71]
  PIN di0[72]
    DIRECTION INPUT ;
    USE SIGNAL ;
    PORT
      LAYER M3 ;
        RECT  13.464 0 13.482 0.144 ;
    END
  END di0[72]
  PIN di0[73]
    DIRECTION INPUT ;
    USE SIGNAL ;
    PORT
      LAYER M5 ;
        RECT  13.584 0 13.608 0.192 ;
    END
  END di0[73]
  PIN di0[74]
    DIRECTION INPUT ;
    USE SIGNAL ;
    PORT
      LAYER M3 ;
        RECT  13.716 0 13.734 0.144 ;
    END
  END di0[74]
  PIN di0[75]
    DIRECTION INPUT ;
    USE SIGNAL ;
    PORT
      LAYER M5 ;
        RECT  13.824 0 13.848 0.192 ;
    END
  END di0[75]
  PIN di0[76]
    DIRECTION INPUT ;
    USE SIGNAL ;
    PORT
      LAYER M3 ;
        RECT  13.968 0 13.986 0.144 ;
    END
  END di0[76]
  PIN di0[77]
    DIRECTION INPUT ;
    USE SIGNAL ;
    PORT
      LAYER M5 ;
        RECT  14.064 0 14.088 0.192 ;
    END
  END di0[77]
  PIN di0[78]
    DIRECTION INPUT ;
    USE SIGNAL ;
    PORT
      LAYER M3 ;
        RECT  14.22 0 14.238 0.144 ;
    END
  END di0[78]
  PIN di0[79]
    DIRECTION INPUT ;
    USE SIGNAL ;
    PORT
      LAYER M5 ;
        RECT  14.352 0 14.376 0.192 ;
    END
  END di0[79]
  PIN di0[7]
    DIRECTION INPUT ;
    USE SIGNAL ;
    PORT
      LAYER M5 ;
        RECT  5.232 0 5.256 0.192 ;
    END
  END di0[7]
  PIN di0[80]
    DIRECTION INPUT ;
    USE SIGNAL ;
    PORT
      LAYER M3 ;
        RECT  14.472 0 14.49 0.144 ;
    END
  END di0[80]
  PIN di0[81]
    DIRECTION INPUT ;
    USE SIGNAL ;
    PORT
      LAYER M5 ;
        RECT  14.592 0 14.616 0.192 ;
    END
  END di0[81]
  PIN di0[82]
    DIRECTION INPUT ;
    USE SIGNAL ;
    PORT
      LAYER M3 ;
        RECT  14.724 0 14.742 0.144 ;
    END
  END di0[82]
  PIN di0[83]
    DIRECTION INPUT ;
    USE SIGNAL ;
    PORT
      LAYER M5 ;
        RECT  14.832 0 14.856 0.192 ;
    END
  END di0[83]
  PIN di0[84]
    DIRECTION INPUT ;
    USE SIGNAL ;
    PORT
      LAYER M3 ;
        RECT  14.976 0 14.994 0.144 ;
    END
  END di0[84]
  PIN di0[85]
    DIRECTION INPUT ;
    USE SIGNAL ;
    PORT
      LAYER M5 ;
        RECT  15.072 0 15.096 0.192 ;
    END
  END di0[85]
  PIN di0[86]
    DIRECTION INPUT ;
    USE SIGNAL ;
    PORT
      LAYER M3 ;
        RECT  15.228 0 15.246 0.144 ;
    END
  END di0[86]
  PIN di0[87]
    DIRECTION INPUT ;
    USE SIGNAL ;
    PORT
      LAYER M5 ;
        RECT  15.36 0 15.384 0.192 ;
    END
  END di0[87]
  PIN di0[88]
    DIRECTION INPUT ;
    USE SIGNAL ;
    PORT
      LAYER M3 ;
        RECT  15.48 0 15.498 0.144 ;
    END
  END di0[88]
  PIN di0[89]
    DIRECTION INPUT ;
    USE SIGNAL ;
    PORT
      LAYER M5 ;
        RECT  15.6 0 15.624 0.192 ;
    END
  END di0[89]
  PIN di0[8]
    DIRECTION INPUT ;
    USE SIGNAL ;
    PORT
      LAYER M3 ;
        RECT  5.4 0 5.418 0.144 ;
    END
  END di0[8]
  PIN di0[90]
    DIRECTION INPUT ;
    USE SIGNAL ;
    PORT
      LAYER M3 ;
        RECT  15.732 0 15.75 0.144 ;
    END
  END di0[90]
  PIN di0[91]
    DIRECTION INPUT ;
    USE SIGNAL ;
    PORT
      LAYER M5 ;
        RECT  15.84 0 15.864 0.192 ;
    END
  END di0[91]
  PIN di0[92]
    DIRECTION INPUT ;
    USE SIGNAL ;
    PORT
      LAYER M3 ;
        RECT  15.984 0 16.002 0.144 ;
    END
  END di0[92]
  PIN di0[93]
    DIRECTION INPUT ;
    USE SIGNAL ;
    PORT
      LAYER M5 ;
        RECT  16.08 0 16.104 0.192 ;
    END
  END di0[93]
  PIN di0[94]
    DIRECTION INPUT ;
    USE SIGNAL ;
    PORT
      LAYER M3 ;
        RECT  16.236 0 16.254 0.144 ;
    END
  END di0[94]
  PIN di0[95]
    DIRECTION INPUT ;
    USE SIGNAL ;
    PORT
      LAYER M5 ;
        RECT  16.368 0 16.392 0.192 ;
    END
  END di0[95]
  PIN di0[96]
    DIRECTION INPUT ;
    USE SIGNAL ;
    PORT
      LAYER M3 ;
        RECT  16.488 0 16.506 0.144 ;
    END
  END di0[96]
  PIN di0[97]
    DIRECTION INPUT ;
    USE SIGNAL ;
    PORT
      LAYER M5 ;
        RECT  16.608 0 16.632 0.192 ;
    END
  END di0[97]
  PIN di0[98]
    DIRECTION INPUT ;
    USE SIGNAL ;
    PORT
      LAYER M3 ;
        RECT  16.74 0 16.758 0.144 ;
    END
  END di0[98]
  PIN di0[99]
    DIRECTION INPUT ;
    USE SIGNAL ;
    PORT
      LAYER M5 ;
        RECT  16.848 0 16.872 0.192 ;
    END
  END di0[99]
  PIN di0[9]
    DIRECTION INPUT ;
    USE SIGNAL ;
    PORT
      LAYER M5 ;
        RECT  5.52 0 5.544 0.192 ;
    END
  END di0[9]
  PIN do0[0]
    DIRECTION OUTPUT ;
    USE SIGNAL ;
    PORT
      LAYER M3 ;
        RECT  4.392 36.576 4.41 36.72 ;
    END
    PORT
      LAYER M3 ;
        RECT  4.356 36.588 4.482 36.653 ;
    END
  END do0[0]
  PIN do0[100]
    DIRECTION OUTPUT ;
    USE SIGNAL ;
    PORT
      LAYER M3 ;
        RECT  16.992 36.576 17.01 36.72 ;
    END
  END do0[100]
  PIN do0[101]
    DIRECTION OUTPUT ;
    USE SIGNAL ;
    PORT
      LAYER M5 ;
        RECT  17.088 36.528 17.112 36.72 ;
    END
  END do0[101]
  PIN do0[102]
    DIRECTION OUTPUT ;
    USE SIGNAL ;
    PORT
      LAYER M3 ;
        RECT  17.244 36.576 17.262 36.72 ;
    END
  END do0[102]
  PIN do0[103]
    DIRECTION OUTPUT ;
    USE SIGNAL ;
    PORT
      LAYER M5 ;
        RECT  17.376 36.528 17.4 36.72 ;
    END
  END do0[103]
  PIN do0[104]
    DIRECTION OUTPUT ;
    USE SIGNAL ;
    PORT
      LAYER M3 ;
        RECT  17.496 36.576 17.514 36.72 ;
    END
  END do0[104]
  PIN do0[105]
    DIRECTION OUTPUT ;
    USE SIGNAL ;
    PORT
      LAYER M5 ;
        RECT  17.616 36.528 17.64 36.72 ;
    END
  END do0[105]
  PIN do0[106]
    DIRECTION OUTPUT ;
    USE SIGNAL ;
    PORT
      LAYER M3 ;
        RECT  17.748 36.576 17.766 36.72 ;
    END
  END do0[106]
  PIN do0[107]
    DIRECTION OUTPUT ;
    USE SIGNAL ;
    PORT
      LAYER M5 ;
        RECT  17.856 36.528 17.88 36.72 ;
    END
  END do0[107]
  PIN do0[108]
    DIRECTION OUTPUT ;
    USE SIGNAL ;
    PORT
      LAYER M3 ;
        RECT  18 36.576 18.018 36.72 ;
    END
  END do0[108]
  PIN do0[109]
    DIRECTION OUTPUT ;
    USE SIGNAL ;
    PORT
      LAYER M5 ;
        RECT  18.096 36.528 18.12 36.72 ;
    END
  END do0[109]
  PIN do0[10]
    DIRECTION OUTPUT ;
    USE SIGNAL ;
    PORT
      LAYER M3 ;
        RECT  5.652 36.576 5.67 36.72 ;
    END
  END do0[10]
  PIN do0[110]
    DIRECTION OUTPUT ;
    USE SIGNAL ;
    PORT
      LAYER M3 ;
        RECT  18.252 36.576 18.27 36.72 ;
    END
  END do0[110]
  PIN do0[111]
    DIRECTION OUTPUT ;
    USE SIGNAL ;
    PORT
      LAYER M5 ;
        RECT  18.384 36.528 18.408 36.72 ;
    END
  END do0[111]
  PIN do0[112]
    DIRECTION OUTPUT ;
    USE SIGNAL ;
    PORT
      LAYER M3 ;
        RECT  18.504 36.576 18.522 36.72 ;
    END
  END do0[112]
  PIN do0[113]
    DIRECTION OUTPUT ;
    USE SIGNAL ;
    PORT
      LAYER M5 ;
        RECT  18.624 36.528 18.648 36.72 ;
    END
  END do0[113]
  PIN do0[114]
    DIRECTION OUTPUT ;
    USE SIGNAL ;
    PORT
      LAYER M3 ;
        RECT  18.756 36.576 18.774 36.72 ;
    END
  END do0[114]
  PIN do0[115]
    DIRECTION OUTPUT ;
    USE SIGNAL ;
    PORT
      LAYER M5 ;
        RECT  18.864 36.528 18.888 36.72 ;
    END
  END do0[115]
  PIN do0[116]
    DIRECTION OUTPUT ;
    USE SIGNAL ;
    PORT
      LAYER M3 ;
        RECT  19.008 36.576 19.026 36.72 ;
    END
  END do0[116]
  PIN do0[117]
    DIRECTION OUTPUT ;
    USE SIGNAL ;
    PORT
      LAYER M5 ;
        RECT  19.104 36.528 19.128 36.72 ;
    END
  END do0[117]
  PIN do0[118]
    DIRECTION OUTPUT ;
    USE SIGNAL ;
    PORT
      LAYER M3 ;
        RECT  19.26 36.576 19.278 36.72 ;
    END
  END do0[118]
  PIN do0[119]
    DIRECTION OUTPUT ;
    USE SIGNAL ;
    PORT
      LAYER M5 ;
        RECT  19.392 36.528 19.416 36.72 ;
    END
  END do0[119]
  PIN do0[11]
    DIRECTION OUTPUT ;
    USE SIGNAL ;
    PORT
      LAYER M5 ;
        RECT  5.76 36.528 5.784 36.72 ;
    END
  END do0[11]
  PIN do0[120]
    DIRECTION OUTPUT ;
    USE SIGNAL ;
    PORT
      LAYER M3 ;
        RECT  19.512 36.576 19.53 36.72 ;
    END
  END do0[120]
  PIN do0[121]
    DIRECTION OUTPUT ;
    USE SIGNAL ;
    PORT
      LAYER M5 ;
        RECT  19.632 36.528 19.656 36.72 ;
    END
  END do0[121]
  PIN do0[122]
    DIRECTION OUTPUT ;
    USE SIGNAL ;
    PORT
      LAYER M3 ;
        RECT  19.764 36.576 19.782 36.72 ;
    END
  END do0[122]
  PIN do0[123]
    DIRECTION OUTPUT ;
    USE SIGNAL ;
    PORT
      LAYER M5 ;
        RECT  19.872 36.528 19.896 36.72 ;
    END
  END do0[123]
  PIN do0[124]
    DIRECTION OUTPUT ;
    USE SIGNAL ;
    PORT
      LAYER M3 ;
        RECT  20.016 36.576 20.034 36.72 ;
    END
  END do0[124]
  PIN do0[125]
    DIRECTION OUTPUT ;
    USE SIGNAL ;
    PORT
      LAYER M5 ;
        RECT  20.112 36.528 20.136 36.72 ;
    END
  END do0[125]
  PIN do0[126]
    DIRECTION OUTPUT ;
    USE SIGNAL ;
    PORT
      LAYER M3 ;
        RECT  20.268 36.576 20.286 36.72 ;
    END
  END do0[126]
  PIN do0[127]
    DIRECTION OUTPUT ;
    USE SIGNAL ;
    PORT
      LAYER M5 ;
        RECT  20.4 36.528 20.424 36.72 ;
    END
  END do0[127]
  PIN do0[128]
    DIRECTION OUTPUT ;
    USE SIGNAL ;
    PORT
      LAYER M3 ;
        RECT  20.52 36.576 20.538 36.72 ;
    END
  END do0[128]
  PIN do0[129]
    DIRECTION OUTPUT ;
    USE SIGNAL ;
    PORT
      LAYER M5 ;
        RECT  20.64 36.528 20.664 36.72 ;
    END
  END do0[129]
  PIN do0[12]
    DIRECTION OUTPUT ;
    USE SIGNAL ;
    PORT
      LAYER M3 ;
        RECT  5.904 36.576 5.922 36.72 ;
    END
    PORT
      LAYER M3 ;
        RECT  5.868 36.588 5.994 36.653 ;
    END
  END do0[12]
  PIN do0[130]
    DIRECTION OUTPUT ;
    USE SIGNAL ;
    PORT
      LAYER M3 ;
        RECT  20.772 36.576 20.79 36.72 ;
    END
  END do0[130]
  PIN do0[131]
    DIRECTION OUTPUT ;
    USE SIGNAL ;
    PORT
      LAYER M5 ;
        RECT  20.88 36.528 20.904 36.72 ;
    END
  END do0[131]
  PIN do0[132]
    DIRECTION OUTPUT ;
    USE SIGNAL ;
    PORT
      LAYER M3 ;
        RECT  21.024 36.576 21.042 36.72 ;
    END
  END do0[132]
  PIN do0[133]
    DIRECTION OUTPUT ;
    USE SIGNAL ;
    PORT
      LAYER M5 ;
        RECT  21.12 36.528 21.144 36.72 ;
    END
  END do0[133]
  PIN do0[134]
    DIRECTION OUTPUT ;
    USE SIGNAL ;
    PORT
      LAYER M3 ;
        RECT  21.276 36.576 21.294 36.72 ;
    END
  END do0[134]
  PIN do0[135]
    DIRECTION OUTPUT ;
    USE SIGNAL ;
    PORT
      LAYER M5 ;
        RECT  21.408 36.528 21.432 36.72 ;
    END
  END do0[135]
  PIN do0[136]
    DIRECTION OUTPUT ;
    USE SIGNAL ;
    PORT
      LAYER M3 ;
        RECT  21.528 36.576 21.546 36.72 ;
    END
  END do0[136]
  PIN do0[137]
    DIRECTION OUTPUT ;
    USE SIGNAL ;
    PORT
      LAYER M5 ;
        RECT  21.648 36.528 21.672 36.72 ;
    END
  END do0[137]
  PIN do0[138]
    DIRECTION OUTPUT ;
    USE SIGNAL ;
    PORT
      LAYER M3 ;
        RECT  21.78 36.576 21.798 36.72 ;
    END
  END do0[138]
  PIN do0[139]
    DIRECTION OUTPUT ;
    USE SIGNAL ;
    PORT
      LAYER M5 ;
        RECT  21.888 36.528 21.912 36.72 ;
    END
  END do0[139]
  PIN do0[13]
    DIRECTION OUTPUT ;
    USE SIGNAL ;
    PORT
      LAYER M5 ;
        RECT  6 36.528 6.024 36.72 ;
    END
  END do0[13]
  PIN do0[140]
    DIRECTION OUTPUT ;
    USE SIGNAL ;
    PORT
      LAYER M3 ;
        RECT  22.032 36.576 22.05 36.72 ;
    END
  END do0[140]
  PIN do0[141]
    DIRECTION OUTPUT ;
    USE SIGNAL ;
    PORT
      LAYER M5 ;
        RECT  22.128 36.528 22.152 36.72 ;
    END
  END do0[141]
  PIN do0[142]
    DIRECTION OUTPUT ;
    USE SIGNAL ;
    PORT
      LAYER M3 ;
        RECT  22.284 36.576 22.302 36.72 ;
    END
  END do0[142]
  PIN do0[143]
    DIRECTION OUTPUT ;
    USE SIGNAL ;
    PORT
      LAYER M5 ;
        RECT  22.416 36.528 22.44 36.72 ;
    END
  END do0[143]
  PIN do0[144]
    DIRECTION OUTPUT ;
    USE SIGNAL ;
    PORT
      LAYER M3 ;
        RECT  22.536 36.576 22.554 36.72 ;
    END
  END do0[144]
  PIN do0[145]
    DIRECTION OUTPUT ;
    USE SIGNAL ;
    PORT
      LAYER M5 ;
        RECT  22.656 36.528 22.68 36.72 ;
    END
  END do0[145]
  PIN do0[146]
    DIRECTION OUTPUT ;
    USE SIGNAL ;
    PORT
      LAYER M3 ;
        RECT  22.788 36.576 22.806 36.72 ;
    END
  END do0[146]
  PIN do0[147]
    DIRECTION OUTPUT ;
    USE SIGNAL ;
    PORT
      LAYER M5 ;
        RECT  22.896 36.528 22.92 36.72 ;
    END
  END do0[147]
  PIN do0[148]
    DIRECTION OUTPUT ;
    USE SIGNAL ;
    PORT
      LAYER M3 ;
        RECT  23.04 36.576 23.058 36.72 ;
    END
  END do0[148]
  PIN do0[149]
    DIRECTION OUTPUT ;
    USE SIGNAL ;
    PORT
      LAYER M5 ;
        RECT  23.136 36.528 23.16 36.72 ;
    END
  END do0[149]
  PIN do0[14]
    DIRECTION OUTPUT ;
    USE SIGNAL ;
    PORT
      LAYER M3 ;
        RECT  6.156 36.576 6.174 36.72 ;
    END
  END do0[14]
  PIN do0[150]
    DIRECTION OUTPUT ;
    USE SIGNAL ;
    PORT
      LAYER M3 ;
        RECT  23.292 36.576 23.31 36.72 ;
    END
  END do0[150]
  PIN do0[151]
    DIRECTION OUTPUT ;
    USE SIGNAL ;
    PORT
      LAYER M5 ;
        RECT  23.424 36.528 23.448 36.72 ;
    END
  END do0[151]
  PIN do0[152]
    DIRECTION OUTPUT ;
    USE SIGNAL ;
    PORT
      LAYER M3 ;
        RECT  23.544 36.576 23.562 36.72 ;
    END
  END do0[152]
  PIN do0[153]
    DIRECTION OUTPUT ;
    USE SIGNAL ;
    PORT
      LAYER M5 ;
        RECT  23.664 36.528 23.688 36.72 ;
    END
  END do0[153]
  PIN do0[154]
    DIRECTION OUTPUT ;
    USE SIGNAL ;
    PORT
      LAYER M3 ;
        RECT  23.796 36.576 23.814 36.72 ;
    END
  END do0[154]
  PIN do0[155]
    DIRECTION OUTPUT ;
    USE SIGNAL ;
    PORT
      LAYER M5 ;
        RECT  23.904 36.528 23.928 36.72 ;
    END
  END do0[155]
  PIN do0[156]
    DIRECTION OUTPUT ;
    USE SIGNAL ;
    PORT
      LAYER M3 ;
        RECT  24.048 36.576 24.066 36.72 ;
    END
  END do0[156]
  PIN do0[157]
    DIRECTION OUTPUT ;
    USE SIGNAL ;
    PORT
      LAYER M5 ;
        RECT  24.144 36.528 24.168 36.72 ;
    END
  END do0[157]
  PIN do0[158]
    DIRECTION OUTPUT ;
    USE SIGNAL ;
    PORT
      LAYER M3 ;
        RECT  24.3 36.576 24.318 36.72 ;
    END
  END do0[158]
  PIN do0[159]
    DIRECTION OUTPUT ;
    USE SIGNAL ;
    PORT
      LAYER M5 ;
        RECT  24.432 36.528 24.456 36.72 ;
    END
  END do0[159]
  PIN do0[15]
    DIRECTION OUTPUT ;
    USE SIGNAL ;
    PORT
      LAYER M5 ;
        RECT  6.24 36.528 6.264 36.72 ;
    END
  END do0[15]
  PIN do0[160]
    DIRECTION OUTPUT ;
    USE SIGNAL ;
    PORT
      LAYER M3 ;
        RECT  24.552 36.576 24.57 36.72 ;
    END
  END do0[160]
  PIN do0[161]
    DIRECTION OUTPUT ;
    USE SIGNAL ;
    PORT
      LAYER M5 ;
        RECT  24.672 36.528 24.696 36.72 ;
    END
  END do0[161]
  PIN do0[162]
    DIRECTION OUTPUT ;
    USE SIGNAL ;
    PORT
      LAYER M3 ;
        RECT  24.804 36.576 24.822 36.72 ;
    END
  END do0[162]
  PIN do0[163]
    DIRECTION OUTPUT ;
    USE SIGNAL ;
    PORT
      LAYER M5 ;
        RECT  24.912 36.528 24.936 36.72 ;
    END
  END do0[163]
  PIN do0[164]
    DIRECTION OUTPUT ;
    USE SIGNAL ;
    PORT
      LAYER M3 ;
        RECT  25.056 36.576 25.074 36.72 ;
    END
  END do0[164]
  PIN do0[165]
    DIRECTION OUTPUT ;
    USE SIGNAL ;
    PORT
      LAYER M5 ;
        RECT  25.152 36.528 25.176 36.72 ;
    END
  END do0[165]
  PIN do0[166]
    DIRECTION OUTPUT ;
    USE SIGNAL ;
    PORT
      LAYER M3 ;
        RECT  25.308 36.576 25.326 36.72 ;
    END
  END do0[166]
  PIN do0[167]
    DIRECTION OUTPUT ;
    USE SIGNAL ;
    PORT
      LAYER M5 ;
        RECT  25.44 36.528 25.464 36.72 ;
    END
  END do0[167]
  PIN do0[168]
    DIRECTION OUTPUT ;
    USE SIGNAL ;
    PORT
      LAYER M3 ;
        RECT  25.56 36.576 25.578 36.72 ;
    END
  END do0[168]
  PIN do0[169]
    DIRECTION OUTPUT ;
    USE SIGNAL ;
    PORT
      LAYER M5 ;
        RECT  25.68 36.528 25.704 36.72 ;
    END
  END do0[169]
  PIN do0[16]
    DIRECTION OUTPUT ;
    USE SIGNAL ;
    PORT
      LAYER M3 ;
        RECT  6.408 36.576 6.426 36.72 ;
    END
  END do0[16]
  PIN do0[170]
    DIRECTION OUTPUT ;
    USE SIGNAL ;
    PORT
      LAYER M3 ;
        RECT  25.812 36.576 25.83 36.72 ;
    END
  END do0[170]
  PIN do0[171]
    DIRECTION OUTPUT ;
    USE SIGNAL ;
    PORT
      LAYER M5 ;
        RECT  25.92 36.528 25.944 36.72 ;
    END
  END do0[171]
  PIN do0[172]
    DIRECTION OUTPUT ;
    USE SIGNAL ;
    PORT
      LAYER M3 ;
        RECT  26.064 36.576 26.082 36.72 ;
    END
  END do0[172]
  PIN do0[173]
    DIRECTION OUTPUT ;
    USE SIGNAL ;
    PORT
      LAYER M5 ;
        RECT  26.16 36.528 26.184 36.72 ;
    END
  END do0[173]
  PIN do0[174]
    DIRECTION OUTPUT ;
    USE SIGNAL ;
    PORT
      LAYER M3 ;
        RECT  26.316 36.576 26.334 36.72 ;
    END
  END do0[174]
  PIN do0[175]
    DIRECTION OUTPUT ;
    USE SIGNAL ;
    PORT
      LAYER M5 ;
        RECT  26.448 36.528 26.472 36.72 ;
    END
  END do0[175]
  PIN do0[176]
    DIRECTION OUTPUT ;
    USE SIGNAL ;
    PORT
      LAYER M3 ;
        RECT  26.568 36.576 26.586 36.72 ;
    END
  END do0[176]
  PIN do0[177]
    DIRECTION OUTPUT ;
    USE SIGNAL ;
    PORT
      LAYER M5 ;
        RECT  26.688 36.528 26.712 36.72 ;
    END
  END do0[177]
  PIN do0[178]
    DIRECTION OUTPUT ;
    USE SIGNAL ;
    PORT
      LAYER M3 ;
        RECT  26.82 36.576 26.838 36.72 ;
    END
  END do0[178]
  PIN do0[179]
    DIRECTION OUTPUT ;
    USE SIGNAL ;
    PORT
      LAYER M5 ;
        RECT  26.928 36.528 26.952 36.72 ;
    END
  END do0[179]
  PIN do0[17]
    DIRECTION OUTPUT ;
    USE SIGNAL ;
    PORT
      LAYER M5 ;
        RECT  6.528 36.528 6.552 36.72 ;
    END
  END do0[17]
  PIN do0[180]
    DIRECTION OUTPUT ;
    USE SIGNAL ;
    PORT
      LAYER M3 ;
        RECT  27.072 36.576 27.09 36.72 ;
    END
  END do0[180]
  PIN do0[181]
    DIRECTION OUTPUT ;
    USE SIGNAL ;
    PORT
      LAYER M5 ;
        RECT  27.168 36.528 27.192 36.72 ;
    END
  END do0[181]
  PIN do0[182]
    DIRECTION OUTPUT ;
    USE SIGNAL ;
    PORT
      LAYER M3 ;
        RECT  27.324 36.576 27.342 36.72 ;
    END
  END do0[182]
  PIN do0[183]
    DIRECTION OUTPUT ;
    USE SIGNAL ;
    PORT
      LAYER M5 ;
        RECT  27.456 36.528 27.48 36.72 ;
    END
  END do0[183]
  PIN do0[184]
    DIRECTION OUTPUT ;
    USE SIGNAL ;
    PORT
      LAYER M3 ;
        RECT  27.576 36.576 27.594 36.72 ;
    END
  END do0[184]
  PIN do0[185]
    DIRECTION OUTPUT ;
    USE SIGNAL ;
    PORT
      LAYER M5 ;
        RECT  27.696 36.528 27.72 36.72 ;
    END
  END do0[185]
  PIN do0[186]
    DIRECTION OUTPUT ;
    USE SIGNAL ;
    PORT
      LAYER M3 ;
        RECT  27.828 36.576 27.846 36.72 ;
    END
  END do0[186]
  PIN do0[187]
    DIRECTION OUTPUT ;
    USE SIGNAL ;
    PORT
      LAYER M5 ;
        RECT  27.936 36.528 27.96 36.72 ;
    END
  END do0[187]
  PIN do0[188]
    DIRECTION OUTPUT ;
    USE SIGNAL ;
    PORT
      LAYER M3 ;
        RECT  28.08 36.576 28.098 36.72 ;
    END
  END do0[188]
  PIN do0[189]
    DIRECTION OUTPUT ;
    USE SIGNAL ;
    PORT
      LAYER M5 ;
        RECT  28.176 36.528 28.2 36.72 ;
    END
  END do0[189]
  PIN do0[18]
    DIRECTION OUTPUT ;
    USE SIGNAL ;
    PORT
      LAYER M3 ;
        RECT  6.66 36.576 6.678 36.72 ;
    END
  END do0[18]
  PIN do0[190]
    DIRECTION OUTPUT ;
    USE SIGNAL ;
    PORT
      LAYER M3 ;
        RECT  28.332 36.576 28.35 36.72 ;
    END
  END do0[190]
  PIN do0[191]
    DIRECTION OUTPUT ;
    USE SIGNAL ;
    PORT
      LAYER M5 ;
        RECT  28.464 36.528 28.488 36.72 ;
    END
  END do0[191]
  PIN do0[192]
    DIRECTION OUTPUT ;
    USE SIGNAL ;
    PORT
      LAYER M3 ;
        RECT  28.584 36.576 28.602 36.72 ;
    END
  END do0[192]
  PIN do0[193]
    DIRECTION OUTPUT ;
    USE SIGNAL ;
    PORT
      LAYER M5 ;
        RECT  28.704 36.528 28.728 36.72 ;
    END
  END do0[193]
  PIN do0[194]
    DIRECTION OUTPUT ;
    USE SIGNAL ;
    PORT
      LAYER M3 ;
        RECT  28.836 36.576 28.854 36.72 ;
    END
  END do0[194]
  PIN do0[195]
    DIRECTION OUTPUT ;
    USE SIGNAL ;
    PORT
      LAYER M5 ;
        RECT  28.944 36.528 28.968 36.72 ;
    END
  END do0[195]
  PIN do0[196]
    DIRECTION OUTPUT ;
    USE SIGNAL ;
    PORT
      LAYER M3 ;
        RECT  29.088 36.576 29.106 36.72 ;
    END
  END do0[196]
  PIN do0[197]
    DIRECTION OUTPUT ;
    USE SIGNAL ;
    PORT
      LAYER M5 ;
        RECT  29.184 36.528 29.208 36.72 ;
    END
  END do0[197]
  PIN do0[198]
    DIRECTION OUTPUT ;
    USE SIGNAL ;
    PORT
      LAYER M3 ;
        RECT  29.34 36.576 29.358 36.72 ;
    END
  END do0[198]
  PIN do0[199]
    DIRECTION OUTPUT ;
    USE SIGNAL ;
    PORT
      LAYER M5 ;
        RECT  29.472 36.528 29.496 36.72 ;
    END
  END do0[199]
  PIN do0[19]
    DIRECTION OUTPUT ;
    USE SIGNAL ;
    PORT
      LAYER M5 ;
        RECT  6.768 36.528 6.792 36.72 ;
    END
  END do0[19]
  PIN do0[1]
    DIRECTION OUTPUT ;
    USE SIGNAL ;
    PORT
      LAYER M5 ;
        RECT  4.512 36.528 4.536 36.72 ;
    END
  END do0[1]
  PIN do0[200]
    DIRECTION OUTPUT ;
    USE SIGNAL ;
    PORT
      LAYER M3 ;
        RECT  29.592 36.576 29.61 36.72 ;
    END
  END do0[200]
  PIN do0[201]
    DIRECTION OUTPUT ;
    USE SIGNAL ;
    PORT
      LAYER M5 ;
        RECT  29.712 36.528 29.736 36.72 ;
    END
  END do0[201]
  PIN do0[202]
    DIRECTION OUTPUT ;
    USE SIGNAL ;
    PORT
      LAYER M3 ;
        RECT  29.844 36.576 29.862 36.72 ;
    END
  END do0[202]
  PIN do0[203]
    DIRECTION OUTPUT ;
    USE SIGNAL ;
    PORT
      LAYER M5 ;
        RECT  29.952 36.528 29.976 36.72 ;
    END
  END do0[203]
  PIN do0[204]
    DIRECTION OUTPUT ;
    USE SIGNAL ;
    PORT
      LAYER M3 ;
        RECT  30.096 36.576 30.114 36.72 ;
    END
  END do0[204]
  PIN do0[205]
    DIRECTION OUTPUT ;
    USE SIGNAL ;
    PORT
      LAYER M5 ;
        RECT  30.192 36.528 30.216 36.72 ;
    END
  END do0[205]
  PIN do0[206]
    DIRECTION OUTPUT ;
    USE SIGNAL ;
    PORT
      LAYER M3 ;
        RECT  30.348 36.576 30.366 36.72 ;
    END
  END do0[206]
  PIN do0[207]
    DIRECTION OUTPUT ;
    USE SIGNAL ;
    PORT
      LAYER M5 ;
        RECT  30.48 36.528 30.504 36.72 ;
    END
  END do0[207]
  PIN do0[208]
    DIRECTION OUTPUT ;
    USE SIGNAL ;
    PORT
      LAYER M3 ;
        RECT  30.6 36.576 30.618 36.72 ;
    END
  END do0[208]
  PIN do0[209]
    DIRECTION OUTPUT ;
    USE SIGNAL ;
    PORT
      LAYER M5 ;
        RECT  30.72 36.528 30.744 36.72 ;
    END
  END do0[209]
  PIN do0[20]
    DIRECTION OUTPUT ;
    USE SIGNAL ;
    PORT
      LAYER M3 ;
        RECT  6.912 36.576 6.93 36.72 ;
    END
  END do0[20]
  PIN do0[210]
    DIRECTION OUTPUT ;
    USE SIGNAL ;
    PORT
      LAYER M3 ;
        RECT  30.852 36.576 30.87 36.72 ;
    END
  END do0[210]
  PIN do0[211]
    DIRECTION OUTPUT ;
    USE SIGNAL ;
    PORT
      LAYER M5 ;
        RECT  30.96 36.528 30.984 36.72 ;
    END
  END do0[211]
  PIN do0[212]
    DIRECTION OUTPUT ;
    USE SIGNAL ;
    PORT
      LAYER M3 ;
        RECT  31.104 36.576 31.122 36.72 ;
    END
  END do0[212]
  PIN do0[213]
    DIRECTION OUTPUT ;
    USE SIGNAL ;
    PORT
      LAYER M5 ;
        RECT  31.2 36.528 31.224 36.72 ;
    END
  END do0[213]
  PIN do0[214]
    DIRECTION OUTPUT ;
    USE SIGNAL ;
    PORT
      LAYER M3 ;
        RECT  31.356 36.576 31.374 36.72 ;
    END
  END do0[214]
  PIN do0[215]
    DIRECTION OUTPUT ;
    USE SIGNAL ;
    PORT
      LAYER M5 ;
        RECT  31.488 36.528 31.512 36.72 ;
    END
  END do0[215]
  PIN do0[216]
    DIRECTION OUTPUT ;
    USE SIGNAL ;
    PORT
      LAYER M3 ;
        RECT  31.608 36.576 31.626 36.72 ;
    END
  END do0[216]
  PIN do0[217]
    DIRECTION OUTPUT ;
    USE SIGNAL ;
    PORT
      LAYER M5 ;
        RECT  31.728 36.528 31.752 36.72 ;
    END
  END do0[217]
  PIN do0[218]
    DIRECTION OUTPUT ;
    USE SIGNAL ;
    PORT
      LAYER M3 ;
        RECT  31.86 36.576 31.878 36.72 ;
    END
  END do0[218]
  PIN do0[219]
    DIRECTION OUTPUT ;
    USE SIGNAL ;
    PORT
      LAYER M5 ;
        RECT  31.968 36.528 31.992 36.72 ;
    END
  END do0[219]
  PIN do0[21]
    DIRECTION OUTPUT ;
    USE SIGNAL ;
    PORT
      LAYER M5 ;
        RECT  7.008 36.528 7.032 36.72 ;
    END
  END do0[21]
  PIN do0[220]
    DIRECTION OUTPUT ;
    USE SIGNAL ;
    PORT
      LAYER M3 ;
        RECT  32.112 36.576 32.13 36.72 ;
    END
  END do0[220]
  PIN do0[221]
    DIRECTION OUTPUT ;
    USE SIGNAL ;
    PORT
      LAYER M5 ;
        RECT  32.256 36.528 32.28 36.72 ;
    END
  END do0[221]
  PIN do0[222]
    DIRECTION OUTPUT ;
    USE SIGNAL ;
    PORT
      LAYER M3 ;
        RECT  32.364 36.576 32.382 36.72 ;
    END
  END do0[222]
  PIN do0[223]
    DIRECTION OUTPUT ;
    USE SIGNAL ;
    PORT
      LAYER M5 ;
        RECT  32.496 36.528 32.52 36.72 ;
    END
  END do0[223]
  PIN do0[224]
    DIRECTION OUTPUT ;
    USE SIGNAL ;
    PORT
      LAYER M3 ;
        RECT  32.616 36.576 32.634 36.72 ;
    END
  END do0[224]
  PIN do0[225]
    DIRECTION OUTPUT ;
    USE SIGNAL ;
    PORT
      LAYER M5 ;
        RECT  32.736 36.528 32.76 36.72 ;
    END
  END do0[225]
  PIN do0[226]
    DIRECTION OUTPUT ;
    USE SIGNAL ;
    PORT
      LAYER M3 ;
        RECT  32.868 36.576 32.886 36.72 ;
    END
  END do0[226]
  PIN do0[227]
    DIRECTION OUTPUT ;
    USE SIGNAL ;
    PORT
      LAYER M5 ;
        RECT  32.976 36.528 33 36.72 ;
    END
  END do0[227]
  PIN do0[228]
    DIRECTION OUTPUT ;
    USE SIGNAL ;
    PORT
      LAYER M3 ;
        RECT  33.12 36.576 33.138 36.72 ;
    END
  END do0[228]
  PIN do0[229]
    DIRECTION OUTPUT ;
    USE SIGNAL ;
    PORT
      LAYER M5 ;
        RECT  33.264 36.528 33.288 36.72 ;
    END
  END do0[229]
  PIN do0[22]
    DIRECTION OUTPUT ;
    USE SIGNAL ;
    PORT
      LAYER M3 ;
        RECT  7.164 36.576 7.182 36.72 ;
    END
  END do0[22]
  PIN do0[230]
    DIRECTION OUTPUT ;
    USE SIGNAL ;
    PORT
      LAYER M3 ;
        RECT  33.372 36.576 33.39 36.72 ;
    END
  END do0[230]
  PIN do0[231]
    DIRECTION OUTPUT ;
    USE SIGNAL ;
    PORT
      LAYER M5 ;
        RECT  33.504 36.528 33.528 36.72 ;
    END
  END do0[231]
  PIN do0[232]
    DIRECTION OUTPUT ;
    USE SIGNAL ;
    PORT
      LAYER M3 ;
        RECT  33.624 36.576 33.642 36.72 ;
    END
  END do0[232]
  PIN do0[233]
    DIRECTION OUTPUT ;
    USE SIGNAL ;
    PORT
      LAYER M5 ;
        RECT  33.744 36.528 33.768 36.72 ;
    END
  END do0[233]
  PIN do0[234]
    DIRECTION OUTPUT ;
    USE SIGNAL ;
    PORT
      LAYER M3 ;
        RECT  33.876 36.576 33.894 36.72 ;
    END
  END do0[234]
  PIN do0[235]
    DIRECTION OUTPUT ;
    USE SIGNAL ;
    PORT
      LAYER M5 ;
        RECT  33.984 36.528 34.008 36.72 ;
    END
  END do0[235]
  PIN do0[236]
    DIRECTION OUTPUT ;
    USE SIGNAL ;
    PORT
      LAYER M3 ;
        RECT  34.128 36.576 34.146 36.72 ;
    END
  END do0[236]
  PIN do0[237]
    DIRECTION OUTPUT ;
    USE SIGNAL ;
    PORT
      LAYER M5 ;
        RECT  34.272 36.528 34.296 36.72 ;
    END
  END do0[237]
  PIN do0[238]
    DIRECTION OUTPUT ;
    USE SIGNAL ;
    PORT
      LAYER M3 ;
        RECT  34.38 36.576 34.398 36.72 ;
    END
  END do0[238]
  PIN do0[239]
    DIRECTION OUTPUT ;
    USE SIGNAL ;
    PORT
      LAYER M5 ;
        RECT  34.512 36.528 34.536 36.72 ;
    END
  END do0[239]
  PIN do0[23]
    DIRECTION OUTPUT ;
    USE SIGNAL ;
    PORT
      LAYER M5 ;
        RECT  7.248 36.528 7.272 36.72 ;
    END
  END do0[23]
  PIN do0[240]
    DIRECTION OUTPUT ;
    USE SIGNAL ;
    PORT
      LAYER M3 ;
        RECT  34.632 36.576 34.65 36.72 ;
    END
  END do0[240]
  PIN do0[241]
    DIRECTION OUTPUT ;
    USE SIGNAL ;
    PORT
      LAYER M5 ;
        RECT  34.752 36.528 34.776 36.72 ;
    END
  END do0[241]
  PIN do0[242]
    DIRECTION OUTPUT ;
    USE SIGNAL ;
    PORT
      LAYER M3 ;
        RECT  34.884 36.576 34.902 36.72 ;
    END
  END do0[242]
  PIN do0[243]
    DIRECTION OUTPUT ;
    USE SIGNAL ;
    PORT
      LAYER M5 ;
        RECT  34.992 36.528 35.016 36.72 ;
    END
  END do0[243]
  PIN do0[244]
    DIRECTION OUTPUT ;
    USE SIGNAL ;
    PORT
      LAYER M3 ;
        RECT  35.136 36.576 35.154 36.72 ;
    END
  END do0[244]
  PIN do0[245]
    DIRECTION OUTPUT ;
    USE SIGNAL ;
    PORT
      LAYER M5 ;
        RECT  35.28 36.528 35.304 36.72 ;
    END
  END do0[245]
  PIN do0[246]
    DIRECTION OUTPUT ;
    USE SIGNAL ;
    PORT
      LAYER M3 ;
        RECT  35.388 36.576 35.406 36.72 ;
    END
  END do0[246]
  PIN do0[247]
    DIRECTION OUTPUT ;
    USE SIGNAL ;
    PORT
      LAYER M5 ;
        RECT  35.52 36.528 35.544 36.72 ;
    END
  END do0[247]
  PIN do0[248]
    DIRECTION OUTPUT ;
    USE SIGNAL ;
    PORT
      LAYER M3 ;
        RECT  35.64 36.576 35.658 36.72 ;
    END
  END do0[248]
  PIN do0[249]
    DIRECTION OUTPUT ;
    USE SIGNAL ;
    PORT
      LAYER M5 ;
        RECT  35.76 36.528 35.784 36.72 ;
    END
  END do0[249]
  PIN do0[24]
    DIRECTION OUTPUT ;
    USE SIGNAL ;
    PORT
      LAYER M3 ;
        RECT  7.416 36.576 7.434 36.72 ;
    END
  END do0[24]
  PIN do0[250]
    DIRECTION OUTPUT ;
    USE SIGNAL ;
    PORT
      LAYER M3 ;
        RECT  35.892 36.576 35.91 36.72 ;
    END
  END do0[250]
  PIN do0[251]
    DIRECTION OUTPUT ;
    USE SIGNAL ;
    PORT
      LAYER M5 ;
        RECT  36 36.528 36.024 36.72 ;
    END
  END do0[251]
  PIN do0[252]
    DIRECTION OUTPUT ;
    USE SIGNAL ;
    PORT
      LAYER M3 ;
        RECT  36.144 36.576 36.162 36.72 ;
    END
  END do0[252]
  PIN do0[253]
    DIRECTION OUTPUT ;
    USE SIGNAL ;
    PORT
      LAYER M5 ;
        RECT  36.288 36.528 36.312 36.72 ;
    END
  END do0[253]
  PIN do0[254]
    DIRECTION OUTPUT ;
    USE SIGNAL ;
    PORT
      LAYER M3 ;
        RECT  36.396 36.576 36.414 36.72 ;
    END
  END do0[254]
  PIN do0[255]
    DIRECTION OUTPUT ;
    USE SIGNAL ;
    PORT
      LAYER M5 ;
        RECT  36.528 36.528 36.552 36.72 ;
    END
  END do0[255]
  PIN do0[25]
    DIRECTION OUTPUT ;
    USE SIGNAL ;
    PORT
      LAYER M5 ;
        RECT  7.536 36.528 7.56 36.72 ;
    END
  END do0[25]
  PIN do0[26]
    DIRECTION OUTPUT ;
    USE SIGNAL ;
    PORT
      LAYER M3 ;
        RECT  7.668 36.576 7.686 36.72 ;
    END
  END do0[26]
  PIN do0[27]
    DIRECTION OUTPUT ;
    USE SIGNAL ;
    PORT
      LAYER M5 ;
        RECT  7.776 36.528 7.8 36.72 ;
    END
  END do0[27]
  PIN do0[28]
    DIRECTION OUTPUT ;
    USE SIGNAL ;
    PORT
      LAYER M3 ;
        RECT  7.92 36.576 7.938 36.72 ;
    END
  END do0[28]
  PIN do0[29]
    DIRECTION OUTPUT ;
    USE SIGNAL ;
    PORT
      LAYER M5 ;
        RECT  8.016 36.528 8.04 36.72 ;
    END
  END do0[29]
  PIN do0[2]
    DIRECTION OUTPUT ;
    USE SIGNAL ;
    PORT
      LAYER M3 ;
        RECT  4.644 36.576 4.662 36.72 ;
    END
  END do0[2]
  PIN do0[30]
    DIRECTION OUTPUT ;
    USE SIGNAL ;
    PORT
      LAYER M3 ;
        RECT  8.172 36.576 8.19 36.72 ;
    END
  END do0[30]
  PIN do0[31]
    DIRECTION OUTPUT ;
    USE SIGNAL ;
    PORT
      LAYER M5 ;
        RECT  8.256 36.528 8.28 36.72 ;
    END
  END do0[31]
  PIN do0[32]
    DIRECTION OUTPUT ;
    USE SIGNAL ;
    PORT
      LAYER M3 ;
        RECT  8.424 36.576 8.442 36.72 ;
    END
  END do0[32]
  PIN do0[33]
    DIRECTION OUTPUT ;
    USE SIGNAL ;
    PORT
      LAYER M5 ;
        RECT  8.544 36.528 8.568 36.72 ;
    END
  END do0[33]
  PIN do0[34]
    DIRECTION OUTPUT ;
    USE SIGNAL ;
    PORT
      LAYER M3 ;
        RECT  8.676 36.576 8.694 36.72 ;
    END
  END do0[34]
  PIN do0[35]
    DIRECTION OUTPUT ;
    USE SIGNAL ;
    PORT
      LAYER M5 ;
        RECT  8.784 36.528 8.808 36.72 ;
    END
  END do0[35]
  PIN do0[36]
    DIRECTION OUTPUT ;
    USE SIGNAL ;
    PORT
      LAYER M3 ;
        RECT  8.928 36.576 8.946 36.72 ;
    END
  END do0[36]
  PIN do0[37]
    DIRECTION OUTPUT ;
    USE SIGNAL ;
    PORT
      LAYER M5 ;
        RECT  9.024 36.528 9.048 36.72 ;
    END
  END do0[37]
  PIN do0[38]
    DIRECTION OUTPUT ;
    USE SIGNAL ;
    PORT
      LAYER M3 ;
        RECT  9.18 36.576 9.198 36.72 ;
    END
  END do0[38]
  PIN do0[39]
    DIRECTION OUTPUT ;
    USE SIGNAL ;
    PORT
      LAYER M5 ;
        RECT  9.264 36.528 9.288 36.72 ;
    END
  END do0[39]
  PIN do0[3]
    DIRECTION OUTPUT ;
    USE SIGNAL ;
    PORT
      LAYER M5 ;
        RECT  4.752 36.528 4.776 36.72 ;
    END
  END do0[3]
  PIN do0[40]
    DIRECTION OUTPUT ;
    USE SIGNAL ;
    PORT
      LAYER M3 ;
        RECT  9.432 36.576 9.45 36.72 ;
    END
  END do0[40]
  PIN do0[41]
    DIRECTION OUTPUT ;
    USE SIGNAL ;
    PORT
      LAYER M5 ;
        RECT  9.552 36.528 9.576 36.72 ;
    END
  END do0[41]
  PIN do0[42]
    DIRECTION OUTPUT ;
    USE SIGNAL ;
    PORT
      LAYER M3 ;
        RECT  9.684 36.576 9.702 36.72 ;
    END
  END do0[42]
  PIN do0[43]
    DIRECTION OUTPUT ;
    USE SIGNAL ;
    PORT
      LAYER M5 ;
        RECT  9.792 36.528 9.816 36.72 ;
    END
  END do0[43]
  PIN do0[44]
    DIRECTION OUTPUT ;
    USE SIGNAL ;
    PORT
      LAYER M3 ;
        RECT  9.936 36.576 9.954 36.72 ;
    END
  END do0[44]
  PIN do0[45]
    DIRECTION OUTPUT ;
    USE SIGNAL ;
    PORT
      LAYER M5 ;
        RECT  10.032 36.528 10.056 36.72 ;
    END
  END do0[45]
  PIN do0[46]
    DIRECTION OUTPUT ;
    USE SIGNAL ;
    PORT
      LAYER M3 ;
        RECT  10.188 36.576 10.206 36.72 ;
    END
  END do0[46]
  PIN do0[47]
    DIRECTION OUTPUT ;
    USE SIGNAL ;
    PORT
      LAYER M5 ;
        RECT  10.32 36.528 10.344 36.72 ;
    END
  END do0[47]
  PIN do0[48]
    DIRECTION OUTPUT ;
    USE SIGNAL ;
    PORT
      LAYER M3 ;
        RECT  10.44 36.576 10.458 36.72 ;
    END
  END do0[48]
  PIN do0[49]
    DIRECTION OUTPUT ;
    USE SIGNAL ;
    PORT
      LAYER M5 ;
        RECT  10.56 36.528 10.584 36.72 ;
    END
  END do0[49]
  PIN do0[4]
    DIRECTION OUTPUT ;
    USE SIGNAL ;
    PORT
      LAYER M3 ;
        RECT  4.896 36.576 4.914 36.72 ;
    END
  END do0[4]
  PIN do0[50]
    DIRECTION OUTPUT ;
    USE SIGNAL ;
    PORT
      LAYER M3 ;
        RECT  10.692 36.576 10.71 36.72 ;
    END
  END do0[50]
  PIN do0[51]
    DIRECTION OUTPUT ;
    USE SIGNAL ;
    PORT
      LAYER M5 ;
        RECT  10.8 36.528 10.824 36.72 ;
    END
  END do0[51]
  PIN do0[52]
    DIRECTION OUTPUT ;
    USE SIGNAL ;
    PORT
      LAYER M3 ;
        RECT  10.944 36.576 10.962 36.72 ;
    END
  END do0[52]
  PIN do0[53]
    DIRECTION OUTPUT ;
    USE SIGNAL ;
    PORT
      LAYER M5 ;
        RECT  11.04 36.528 11.064 36.72 ;
    END
  END do0[53]
  PIN do0[54]
    DIRECTION OUTPUT ;
    USE SIGNAL ;
    PORT
      LAYER M3 ;
        RECT  11.196 36.576 11.214 36.72 ;
    END
  END do0[54]
  PIN do0[55]
    DIRECTION OUTPUT ;
    USE SIGNAL ;
    PORT
      LAYER M5 ;
        RECT  11.328 36.528 11.352 36.72 ;
    END
  END do0[55]
  PIN do0[56]
    DIRECTION OUTPUT ;
    USE SIGNAL ;
    PORT
      LAYER M3 ;
        RECT  11.448 36.576 11.466 36.72 ;
    END
  END do0[56]
  PIN do0[57]
    DIRECTION OUTPUT ;
    USE SIGNAL ;
    PORT
      LAYER M5 ;
        RECT  11.568 36.528 11.592 36.72 ;
    END
  END do0[57]
  PIN do0[58]
    DIRECTION OUTPUT ;
    USE SIGNAL ;
    PORT
      LAYER M3 ;
        RECT  11.7 36.576 11.718 36.72 ;
    END
  END do0[58]
  PIN do0[59]
    DIRECTION OUTPUT ;
    USE SIGNAL ;
    PORT
      LAYER M5 ;
        RECT  11.808 36.528 11.832 36.72 ;
    END
  END do0[59]
  PIN do0[5]
    DIRECTION OUTPUT ;
    USE SIGNAL ;
    PORT
      LAYER M5 ;
        RECT  4.992 36.528 5.016 36.72 ;
    END
  END do0[5]
  PIN do0[60]
    DIRECTION OUTPUT ;
    USE SIGNAL ;
    PORT
      LAYER M3 ;
        RECT  11.952 36.576 11.97 36.72 ;
    END
  END do0[60]
  PIN do0[61]
    DIRECTION OUTPUT ;
    USE SIGNAL ;
    PORT
      LAYER M5 ;
        RECT  12.048 36.528 12.072 36.72 ;
    END
  END do0[61]
  PIN do0[62]
    DIRECTION OUTPUT ;
    USE SIGNAL ;
    PORT
      LAYER M3 ;
        RECT  12.204 36.576 12.222 36.72 ;
    END
  END do0[62]
  PIN do0[63]
    DIRECTION OUTPUT ;
    USE SIGNAL ;
    PORT
      LAYER M5 ;
        RECT  12.336 36.528 12.36 36.72 ;
    END
  END do0[63]
  PIN do0[64]
    DIRECTION OUTPUT ;
    USE SIGNAL ;
    PORT
      LAYER M3 ;
        RECT  12.456 36.576 12.474 36.72 ;
    END
  END do0[64]
  PIN do0[65]
    DIRECTION OUTPUT ;
    USE SIGNAL ;
    PORT
      LAYER M5 ;
        RECT  12.576 36.528 12.6 36.72 ;
    END
  END do0[65]
  PIN do0[66]
    DIRECTION OUTPUT ;
    USE SIGNAL ;
    PORT
      LAYER M3 ;
        RECT  12.708 36.576 12.726 36.72 ;
    END
  END do0[66]
  PIN do0[67]
    DIRECTION OUTPUT ;
    USE SIGNAL ;
    PORT
      LAYER M5 ;
        RECT  12.816 36.528 12.84 36.72 ;
    END
  END do0[67]
  PIN do0[68]
    DIRECTION OUTPUT ;
    USE SIGNAL ;
    PORT
      LAYER M3 ;
        RECT  12.96 36.576 12.978 36.72 ;
    END
  END do0[68]
  PIN do0[69]
    DIRECTION OUTPUT ;
    USE SIGNAL ;
    PORT
      LAYER M5 ;
        RECT  13.056 36.528 13.08 36.72 ;
    END
  END do0[69]
  PIN do0[6]
    DIRECTION OUTPUT ;
    USE SIGNAL ;
    PORT
      LAYER M3 ;
        RECT  5.148 36.576 5.166 36.72 ;
    END
  END do0[6]
  PIN do0[70]
    DIRECTION OUTPUT ;
    USE SIGNAL ;
    PORT
      LAYER M3 ;
        RECT  13.212 36.576 13.23 36.72 ;
    END
  END do0[70]
  PIN do0[71]
    DIRECTION OUTPUT ;
    USE SIGNAL ;
    PORT
      LAYER M5 ;
        RECT  13.344 36.528 13.368 36.72 ;
    END
  END do0[71]
  PIN do0[72]
    DIRECTION OUTPUT ;
    USE SIGNAL ;
    PORT
      LAYER M3 ;
        RECT  13.464 36.576 13.482 36.72 ;
    END
  END do0[72]
  PIN do0[73]
    DIRECTION OUTPUT ;
    USE SIGNAL ;
    PORT
      LAYER M5 ;
        RECT  13.584 36.528 13.608 36.72 ;
    END
  END do0[73]
  PIN do0[74]
    DIRECTION OUTPUT ;
    USE SIGNAL ;
    PORT
      LAYER M3 ;
        RECT  13.716 36.576 13.734 36.72 ;
    END
  END do0[74]
  PIN do0[75]
    DIRECTION OUTPUT ;
    USE SIGNAL ;
    PORT
      LAYER M5 ;
        RECT  13.824 36.528 13.848 36.72 ;
    END
  END do0[75]
  PIN do0[76]
    DIRECTION OUTPUT ;
    USE SIGNAL ;
    PORT
      LAYER M3 ;
        RECT  13.968 36.576 13.986 36.72 ;
    END
  END do0[76]
  PIN do0[77]
    DIRECTION OUTPUT ;
    USE SIGNAL ;
    PORT
      LAYER M5 ;
        RECT  14.064 36.528 14.088 36.72 ;
    END
  END do0[77]
  PIN do0[78]
    DIRECTION OUTPUT ;
    USE SIGNAL ;
    PORT
      LAYER M3 ;
        RECT  14.22 36.576 14.238 36.72 ;
    END
  END do0[78]
  PIN do0[79]
    DIRECTION OUTPUT ;
    USE SIGNAL ;
    PORT
      LAYER M5 ;
        RECT  14.352 36.528 14.376 36.72 ;
    END
  END do0[79]
  PIN do0[7]
    DIRECTION OUTPUT ;
    USE SIGNAL ;
    PORT
      LAYER M5 ;
        RECT  5.232 36.528 5.256 36.72 ;
    END
  END do0[7]
  PIN do0[80]
    DIRECTION OUTPUT ;
    USE SIGNAL ;
    PORT
      LAYER M3 ;
        RECT  14.472 36.576 14.49 36.72 ;
    END
  END do0[80]
  PIN do0[81]
    DIRECTION OUTPUT ;
    USE SIGNAL ;
    PORT
      LAYER M5 ;
        RECT  14.592 36.528 14.616 36.72 ;
    END
  END do0[81]
  PIN do0[82]
    DIRECTION OUTPUT ;
    USE SIGNAL ;
    PORT
      LAYER M3 ;
        RECT  14.724 36.576 14.742 36.72 ;
    END
  END do0[82]
  PIN do0[83]
    DIRECTION OUTPUT ;
    USE SIGNAL ;
    PORT
      LAYER M5 ;
        RECT  14.832 36.528 14.856 36.72 ;
    END
  END do0[83]
  PIN do0[84]
    DIRECTION OUTPUT ;
    USE SIGNAL ;
    PORT
      LAYER M3 ;
        RECT  14.976 36.576 14.994 36.72 ;
    END
  END do0[84]
  PIN do0[85]
    DIRECTION OUTPUT ;
    USE SIGNAL ;
    PORT
      LAYER M5 ;
        RECT  15.072 36.528 15.096 36.72 ;
    END
  END do0[85]
  PIN do0[86]
    DIRECTION OUTPUT ;
    USE SIGNAL ;
    PORT
      LAYER M3 ;
        RECT  15.228 36.576 15.246 36.72 ;
    END
  END do0[86]
  PIN do0[87]
    DIRECTION OUTPUT ;
    USE SIGNAL ;
    PORT
      LAYER M5 ;
        RECT  15.36 36.528 15.384 36.72 ;
    END
  END do0[87]
  PIN do0[88]
    DIRECTION OUTPUT ;
    USE SIGNAL ;
    PORT
      LAYER M3 ;
        RECT  15.48 36.576 15.498 36.72 ;
    END
  END do0[88]
  PIN do0[89]
    DIRECTION OUTPUT ;
    USE SIGNAL ;
    PORT
      LAYER M5 ;
        RECT  15.6 36.528 15.624 36.72 ;
    END
  END do0[89]
  PIN do0[8]
    DIRECTION OUTPUT ;
    USE SIGNAL ;
    PORT
      LAYER M3 ;
        RECT  5.4 36.576 5.418 36.72 ;
    END
  END do0[8]
  PIN do0[90]
    DIRECTION OUTPUT ;
    USE SIGNAL ;
    PORT
      LAYER M3 ;
        RECT  15.732 36.576 15.75 36.72 ;
    END
  END do0[90]
  PIN do0[91]
    DIRECTION OUTPUT ;
    USE SIGNAL ;
    PORT
      LAYER M5 ;
        RECT  15.84 36.528 15.864 36.72 ;
    END
  END do0[91]
  PIN do0[92]
    DIRECTION OUTPUT ;
    USE SIGNAL ;
    PORT
      LAYER M3 ;
        RECT  15.984 36.576 16.002 36.72 ;
    END
  END do0[92]
  PIN do0[93]
    DIRECTION OUTPUT ;
    USE SIGNAL ;
    PORT
      LAYER M5 ;
        RECT  16.08 36.528 16.104 36.72 ;
    END
  END do0[93]
  PIN do0[94]
    DIRECTION OUTPUT ;
    USE SIGNAL ;
    PORT
      LAYER M3 ;
        RECT  16.236 36.576 16.254 36.72 ;
    END
  END do0[94]
  PIN do0[95]
    DIRECTION OUTPUT ;
    USE SIGNAL ;
    PORT
      LAYER M5 ;
        RECT  16.368 36.528 16.392 36.72 ;
    END
  END do0[95]
  PIN do0[96]
    DIRECTION OUTPUT ;
    USE SIGNAL ;
    PORT
      LAYER M3 ;
        RECT  16.488 36.576 16.506 36.72 ;
    END
  END do0[96]
  PIN do0[97]
    DIRECTION OUTPUT ;
    USE SIGNAL ;
    PORT
      LAYER M5 ;
        RECT  16.608 36.528 16.632 36.72 ;
    END
  END do0[97]
  PIN do0[98]
    DIRECTION OUTPUT ;
    USE SIGNAL ;
    PORT
      LAYER M3 ;
        RECT  16.74 36.576 16.758 36.72 ;
    END
  END do0[98]
  PIN do0[99]
    DIRECTION OUTPUT ;
    USE SIGNAL ;
    PORT
      LAYER M5 ;
        RECT  16.848 36.528 16.872 36.72 ;
    END
  END do0[99]
  PIN do0[9]
    DIRECTION OUTPUT ;
    USE SIGNAL ;
    PORT
      LAYER M5 ;
        RECT  5.52 36.528 5.544 36.72 ;
    END
  END do0[9]
  PIN fi0[0]
    DIRECTION INPUT ;
    USE SIGNAL ;
    PORT
      LAYER M3 ;
        RECT  36.648 0 36.666 0.144 ;
    END
  END fi0[0]
  PIN fo0[0]
    DIRECTION OUTPUT ;
    USE SIGNAL ;
    PORT
      LAYER M3 ;
        RECT  36.648 36.576 36.666 36.72 ;
    END
  END fo0[0]
  PIN VDD
    DIRECTION INOUT ;
    USE POWER ;
    PORT
      LAYER M5 ;
        RECT  37.692 2.151 37.812 34.569 ;
        RECT  34.992 2.151 35.112 34.569 ;
        RECT  32.292 2.151 32.412 34.569 ;
        RECT  29.592 2.151 29.712 34.569 ;
        RECT  26.892 2.151 27.012 34.569 ;
        RECT  24.192 2.151 24.312 34.569 ;
        RECT  21.492 2.151 21.612 34.569 ;
        RECT  18.792 2.151 18.912 34.569 ;
        RECT  16.092 2.151 16.212 34.569 ;
        RECT  13.392 2.151 13.512 34.569 ;
        RECT  10.692 2.151 10.812 34.569 ;
        RECT  7.992 2.151 8.112 34.569 ;
        RECT  5.292 2.151 5.412 34.569 ;
        RECT  2.592 2.151 2.712 34.569 ;
    END
  END VDD
  PIN VSS
    DIRECTION INOUT ;
    USE GROUND ;
    PORT
      LAYER M5 ;
        RECT  37.5 2.137 37.62 34.583 ;
        RECT  34.8 2.137 34.92 34.583 ;
        RECT  32.1 2.137 32.22 34.583 ;
        RECT  29.4 2.137 29.52 34.583 ;
        RECT  26.7 2.137 26.82 34.583 ;
        RECT  24 2.137 24.12 34.583 ;
        RECT  21.3 2.137 21.42 34.583 ;
        RECT  18.6 2.137 18.72 34.583 ;
        RECT  15.9 2.137 16.02 34.583 ;
        RECT  13.2 2.137 13.32 34.583 ;
        RECT  10.5 2.137 10.62 34.583 ;
        RECT  7.8 2.137 7.92 34.583 ;
        RECT  5.1 2.137 5.22 34.583 ;
        RECT  2.4 2.137 2.52 34.583 ;
    END
  END VSS
  # OT_OBS_CLOSED layer=M5 d_um=1.536 added=57
  OBS
    LAYER RVTN ;
     RECT  2.16 2.16 38.88 2.295 ;
     RECT  2.16 2.565 38.88 2.835 ;
     RECT  2.16 3.105 38.88 3.375 ;
     RECT  2.16 3.645 38.88 3.915 ;
     RECT  2.16 4.185 38.88 4.455 ;
     RECT  2.16 4.725 38.88 4.995 ;
     RECT  2.16 5.265 38.88 5.535 ;
     RECT  2.16 5.805 38.88 6.075 ;
     RECT  2.16 6.345 38.88 6.615 ;
     RECT  2.16 6.885 38.88 7.155 ;
     RECT  2.16 7.425 38.88 7.695 ;
     RECT  2.16 7.965 38.88 8.235 ;
     RECT  2.16 8.505 38.88 8.775 ;
     RECT  2.16 9.045 38.88 9.315 ;
     RECT  2.16 9.585 38.88 9.855 ;
     RECT  2.16 10.125 38.88 10.395 ;
     RECT  2.16 10.665 38.88 10.935 ;
     RECT  2.16 11.205 38.88 11.475 ;
     RECT  2.16 11.745 38.88 12.015 ;
     RECT  2.16 12.285 38.88 12.555 ;
     RECT  2.16 12.825 38.88 13.095 ;
     RECT  2.16 13.365 38.88 13.635 ;
     RECT  2.16 13.905 38.88 14.175 ;
     RECT  2.16 14.445 38.88 14.715 ;
     RECT  2.16 14.985 38.88 15.255 ;
     RECT  2.16 15.525 38.88 15.795 ;
     RECT  2.16 16.065 38.88 16.335 ;
     RECT  2.16 16.605 38.88 16.875 ;
     RECT  2.16 17.145 38.88 17.415 ;
     RECT  2.16 17.685 38.88 17.955 ;
     RECT  2.16 18.225 38.88 18.495 ;
     RECT  2.16 18.765 38.88 19.035 ;
     RECT  2.16 19.305 38.88 19.575 ;
     RECT  2.16 19.845 38.88 20.115 ;
     RECT  2.16 20.385 38.88 20.655 ;
     RECT  2.16 20.925 38.88 21.195 ;
     RECT  2.16 21.465 38.88 21.735 ;
     RECT  2.16 22.005 38.88 22.275 ;
     RECT  2.16 22.545 38.88 22.815 ;
     RECT  2.16 23.085 38.88 23.355 ;
     RECT  2.16 23.625 38.88 23.895 ;
     RECT  2.16 24.165 38.88 24.435 ;
     RECT  2.16 24.705 38.88 24.975 ;
     RECT  2.16 25.245 38.88 25.515 ;
     RECT  2.16 25.785 38.88 26.055 ;
     RECT  2.16 26.325 38.88 26.595 ;
     RECT  2.16 26.865 38.88 27.135 ;
     RECT  2.16 27.405 38.88 27.675 ;
     RECT  2.16 27.945 38.88 28.215 ;
     RECT  2.16 28.485 38.88 28.755 ;
     RECT  2.16 29.025 38.88 29.295 ;
     RECT  2.16 29.565 38.88 29.835 ;
     RECT  2.16 30.105 38.88 30.375 ;
     RECT  2.16 30.645 38.88 30.915 ;
     RECT  2.16 31.185 38.88 31.455 ;
     RECT  2.16 31.725 38.88 31.995 ;
     RECT  2.16 32.265 38.88 32.535 ;
     RECT  2.16 32.805 38.88 33.075 ;
     RECT  2.16 33.345 38.88 33.615 ;
     RECT  2.16 33.885 38.88 34.155 ;
     RECT  2.16 34.425 38.88 34.56 ;
    LAYER RVTP ;
     RECT  2.16 2.295 38.88 2.565 ;
     RECT  2.16 2.835 38.88 3.105 ;
     RECT  2.16 3.375 38.88 3.645 ;
     RECT  2.16 3.915 38.88 4.185 ;
     RECT  2.16 4.455 38.88 4.725 ;
     RECT  2.16 4.995 38.88 5.265 ;
     RECT  2.16 5.535 38.88 5.805 ;
     RECT  2.16 6.075 38.88 6.345 ;
     RECT  2.16 6.615 38.88 6.885 ;
     RECT  2.16 7.155 38.88 7.425 ;
     RECT  2.16 7.695 38.88 7.965 ;
     RECT  2.16 8.235 38.88 8.505 ;
     RECT  2.16 8.775 38.88 9.045 ;
     RECT  2.16 9.315 38.88 9.585 ;
     RECT  2.16 9.855 38.88 10.125 ;
     RECT  2.16 10.395 38.88 10.665 ;
     RECT  2.16 10.935 38.88 11.205 ;
     RECT  2.16 11.475 38.88 11.745 ;
     RECT  2.16 12.015 38.88 12.285 ;
     RECT  2.16 12.555 38.88 12.825 ;
     RECT  2.16 13.095 38.88 13.365 ;
     RECT  2.16 13.635 38.88 13.905 ;
     RECT  2.16 14.175 38.88 14.445 ;
     RECT  2.16 14.715 38.88 14.985 ;
     RECT  2.16 15.255 38.88 15.525 ;
     RECT  2.16 15.795 38.88 16.065 ;
     RECT  2.16 16.335 38.88 16.605 ;
     RECT  2.16 16.875 38.88 17.145 ;
     RECT  2.16 17.415 38.88 17.685 ;
     RECT  2.16 17.955 38.88 18.225 ;
     RECT  2.16 18.495 38.88 18.765 ;
     RECT  2.16 19.035 38.88 19.305 ;
     RECT  2.16 19.575 38.88 19.845 ;
     RECT  2.16 20.115 38.88 20.385 ;
     RECT  2.16 20.655 38.88 20.925 ;
     RECT  2.16 21.195 38.88 21.465 ;
     RECT  2.16 21.735 38.88 22.005 ;
     RECT  2.16 22.275 38.88 22.545 ;
     RECT  2.16 22.815 38.88 23.085 ;
     RECT  2.16 23.355 38.88 23.625 ;
     RECT  2.16 23.895 38.88 24.165 ;
     RECT  2.16 24.435 38.88 24.705 ;
     RECT  2.16 24.975 38.88 25.245 ;
     RECT  2.16 25.515 38.88 25.785 ;
     RECT  2.16 26.055 38.88 26.325 ;
     RECT  2.16 26.595 38.88 26.865 ;
     RECT  2.16 27.135 38.88 27.405 ;
     RECT  2.16 27.675 38.88 27.945 ;
     RECT  2.16 28.215 38.88 28.485 ;
     RECT  2.16 28.755 38.88 29.025 ;
     RECT  2.16 29.295 38.88 29.565 ;
     RECT  2.16 29.835 38.88 30.105 ;
     RECT  2.16 30.375 38.88 30.645 ;
     RECT  2.16 30.915 38.88 31.185 ;
     RECT  2.16 31.455 38.88 31.725 ;
     RECT  2.16 31.995 38.88 32.265 ;
     RECT  2.16 32.535 38.88 32.805 ;
     RECT  2.16 33.075 38.88 33.345 ;
     RECT  2.16 33.615 38.88 33.885 ;
     RECT  2.16 34.155 38.88 34.425 ;
    LAYER M1 ;
     RECT  2.16 2.151 38.88 34.569 ;
    LAYER M2 ;
     RECT  2.16 2.151 4.027 34.569 ;
     RECT  4.351 36.63 4.387 36.648 ;
     RECT  4.027 1.728 4.415 34.569 ;
     RECT  4.387 36.558 4.487 36.648 ;
     RECT  4.415 2.106 4.711 34.569 ;
     RECT  4.711 2.106 4.919 34.794 ;
     RECT  4.919 2.106 5.279 34.65 ;
     RECT  5.279 2.106 5.431 34.569 ;
     RECT  5.143 0.144 5.603 0.162 ;
     RECT  5.431 1.728 5.675 34.569 ;
     RECT  5.863 36.63 5.899 36.648 ;
     RECT  5.899 36.558 5.999 36.648 ;
     RECT  7.087 0.144 7.187 0.162 ;
     RECT  5.675 2.151 7.627 34.569 ;
     RECT  7.627 2.151 7.663 34.65 ;
     RECT  7.663 1.728 7.943 34.65 ;
     RECT  7.943 1.728 8.915 34.569 ;
     RECT  8.915 1.8 9.167 34.569 ;
     RECT  9.427 0.144 9.527 0.162 ;
     RECT  10.471 0.144 10.715 0.162 ;
     RECT  9.167 2.151 13.207 34.569 ;
     RECT  12.703 0.144 13.379 0.162 ;
     RECT  13.207 2.151 13.459 34.65 ;
     RECT  13.459 1.728 13.775 34.65 ;
     RECT  13.775 2.151 14.063 34.65 ;
     RECT  14.143 0.144 14.243 0.162 ;
     RECT  14.063 2.151 15.979 34.569 ;
     RECT  15.979 0.144 16.079 0.162 ;
     RECT  15.979 2.151 16.483 34.65 ;
     RECT  16.483 1.728 16.511 34.65 ;
     RECT  16.511 1.728 16.619 34.569 ;
     RECT  16.619 2.106 17.303 34.569 ;
     RECT  17.303 2.151 18.247 34.569 ;
     RECT  19.255 0.144 19.607 0.162 ;
     RECT  18.247 1.728 19.931 34.569 ;
     RECT  19.931 2.151 21.523 34.569 ;
     RECT  21.775 0.144 22.091 0.162 ;
     RECT  21.523 1.728 23.063 34.569 ;
     RECT  23.035 0.144 23.171 0.162 ;
     RECT  23.063 2.151 23.899 34.569 ;
     RECT  24.043 0.144 24.395 0.162 ;
     RECT  25.303 0.144 25.403 0.162 ;
     RECT  23.899 2.151 25.555 34.686 ;
     RECT  25.555 2.151 25.663 34.794 ;
     RECT  26.815 0.144 27.059 0.162 ;
     RECT  27.067 36.558 27.103 36.576 ;
     RECT  27.103 36.558 27.203 36.648 ;
     RECT  25.663 2.151 27.671 34.839 ;
     RECT  27.671 2.151 27.823 34.794 ;
     RECT  27.823 1.656 27.959 34.794 ;
     RECT  27.959 2.151 28.579 34.794 ;
     RECT  28.579 2.151 29.039 34.839 ;
     RECT  28.327 0.144 29.371 0.162 ;
     RECT  29.371 0.144 29.579 0.234 ;
     RECT  29.579 0.216 29.615 0.234 ;
     RECT  29.039 2.151 29.839 34.794 ;
     RECT  29.839 2.151 29.975 34.839 ;
     RECT  29.975 2.151 30.091 34.794 ;
     RECT  30.091 1.728 31.055 34.794 ;
     RECT  31.055 2.151 32.107 34.794 ;
     RECT  31.603 0.144 32.279 0.162 ;
     RECT  32.107 2.151 32.359 35.379 ;
     RECT  32.359 1.728 32.675 35.379 ;
     RECT  32.863 36.558 32.899 36.576 ;
     RECT  32.899 36.558 32.999 36.648 ;
     RECT  32.675 2.151 33.539 35.379 ;
     RECT  33.539 2.151 34.123 34.884 ;
     RECT  34.123 1.728 34.295 34.884 ;
     RECT  34.627 0.144 34.979 0.162 ;
     RECT  34.295 2.151 35.131 34.884 ;
     RECT  35.131 2.151 35.231 34.92 ;
     RECT  35.815 0.144 35.915 0.162 ;
     RECT  35.231 2.151 37.679 34.884 ;
     RECT  37.679 2.151 38.183 34.839 ;
     RECT  38.183 2.151 38.435 34.686 ;
     RECT  38.435 2.151 38.88 34.569 ;
     RECT  38.88 19.08 38.903 19.098 ;
     RECT  38.88 27.072 38.939 27.09 ;
     RECT  38.88 33.156 38.939 34.524 ;
     RECT  38.88 6.552 38.975 6.642 ;
     RECT  38.88 30.924 38.975 31.014 ;
     RECT  38.939 33.39 38.975 34.524 ;
     RECT  38.975 30.924 39.047 30.942 ;
     RECT  38.975 33.39 39.047 33.408 ;
     RECT  38.975 6.552 39.371 6.57 ;
     RECT  38.975 34.236 39.371 34.524 ;
     RECT  38.88 7.668 39.407 7.686 ;
     RECT  39.371 34.506 39.407 34.524 ;
    LAYER M3 ;
     RECT  4.392 0.108 36.666 0.317 ;
     RECT  4.392 0.317 36.414 1.723 ;
     RECT  37.515 2.143 37.605 2.191 ;
     RECT  37.152 2.191 37.605 2.227 ;
     RECT  4.032 1.723 36.414 2.263 ;
     RECT  37.152 2.227 37.638 2.263 ;
     RECT  4.032 2.263 37.638 2.371 ;
     RECT  2.415 2.143 2.505 2.413 ;
     RECT  3.708 2.371 38.07 2.641 ;
     RECT  3.708 2.641 38.214 2.767 ;
     RECT  3.708 2.767 38.322 3.145 ;
     RECT  3.492 3.145 38.322 3.379 ;
     RECT  3.492 3.379 38.43 3.437 ;
     RECT  4.104 3.437 38.43 3.965 ;
     RECT  4.104 3.965 38.142 4.261 ;
     RECT  4.068 4.261 38.142 4.379 ;
     RECT  2.415 2.413 2.697 4.531 ;
     RECT  4.104 4.379 38.142 4.801 ;
     RECT  4.104 4.801 38.43 5.341 ;
     RECT  4.104 5.341 38.646 5.693 ;
     RECT  39.348 6.547 39.366 6.619 ;
     RECT  2.415 4.531 3.294 6.691 ;
     RECT  4.104 5.693 38.142 6.691 ;
     RECT  2.415 6.691 38.142 7.259 ;
     RECT  35.856 7.259 38.142 7.421 ;
     RECT  38.952 6.619 39.366 7.663 ;
     RECT  35.928 7.421 38.142 7.735 ;
     RECT  38.952 7.663 39.402 7.735 ;
     RECT  2.415 7.259 35.097 8.429 ;
     RECT  14.328 8.429 35.097 9.211 ;
     RECT  14.328 9.211 35.154 9.293 ;
     RECT  35.928 7.735 39.402 9.779 ;
     RECT  14.652 9.293 35.154 9.917 ;
     RECT  14.652 9.917 28.494 10.637 ;
     RECT  14.652 10.637 28.386 11.705 ;
     RECT  29.415 9.917 35.154 11.777 ;
     RECT  25.164 11.705 28.386 27.095 ;
     RECT  26.715 27.095 28.386 28.211 ;
     RECT  14.652 11.705 24.297 28.493 ;
     RECT  31.608 11.777 35.154 29.065 ;
     RECT  14.688 28.493 24.297 29.363 ;
     RECT  26.715 28.211 28.278 29.363 ;
     RECT  2.415 8.429 13.497 29.645 ;
     RECT  31.608 29.065 35.298 30.271 ;
     RECT  36.18 9.779 39.402 30.271 ;
     RECT  27.864 29.363 28.278 30.479 ;
     RECT  22.32 29.363 24.297 30.919 ;
     RECT  25.164 27.095 25.686 30.919 ;
     RECT  14.688 29.363 21.597 31.117 ;
     RECT  14.508 31.117 21.597 31.189 ;
     RECT  26.715 29.363 26.997 31.225 ;
     RECT  27.864 30.479 27.882 31.225 ;
     RECT  14.472 31.189 21.597 31.261 ;
     RECT  26.715 31.225 28.062 31.261 ;
     RECT  31.608 30.271 39.402 31.339 ;
     RECT  2.415 29.645 12.402 31.387 ;
     RECT  13.215 29.645 13.497 31.387 ;
     RECT  14.256 31.261 21.597 31.387 ;
     RECT  22.32 30.919 25.686 31.387 ;
     RECT  26.715 31.261 28.206 31.387 ;
     RECT  29.415 11.777 30.69 31.387 ;
     RECT  2.415 31.387 13.497 31.459 ;
     RECT  14.22 31.387 28.206 31.459 ;
     RECT  29.232 31.387 30.69 31.459 ;
     RECT  31.536 31.339 39.402 31.459 ;
     RECT  2.415 31.459 28.206 31.657 ;
     RECT  2.415 31.657 28.386 31.729 ;
     RECT  29.232 31.459 39.402 31.729 ;
     RECT  2.415 31.729 39.402 34.079 ;
     RECT  4.068 34.079 39.402 34.187 ;
     RECT  39.348 34.187 39.402 34.259 ;
     RECT  2.415 34.079 2.697 34.307 ;
     RECT  4.068 34.187 38.43 34.349 ;
     RECT  26.496 34.349 38.43 34.421 ;
     RECT  26.496 34.421 36.594 34.493 ;
     RECT  4.104 34.349 25.686 34.529 ;
     RECT  39.384 34.259 39.402 34.529 ;
     RECT  2.415 34.307 2.505 34.577 ;
     RECT  4.356 34.529 16.506 34.577 ;
     RECT  28.584 34.493 36.594 34.577 ;
     RECT  37.515 34.421 38.43 34.577 ;
     RECT  29.844 34.577 36.594 34.619 ;
     RECT  15.984 34.577 16.506 34.655 ;
     RECT  37.656 34.577 38.43 34.691 ;
     RECT  29.844 34.619 36.486 34.733 ;
     RECT  26.496 34.493 27.846 34.763 ;
     RECT  31.104 34.733 36.486 34.781 ;
     RECT  17.244 34.529 25.686 34.844 ;
     RECT  37.656 34.691 38.178 34.844 ;
     RECT  31.104 34.781 36.414 34.877 ;
     RECT  37.656 34.844 37.674 34.889 ;
     RECT  4.356 34.577 15.246 35.323 ;
     RECT  15.984 34.655 16.002 35.323 ;
     RECT  17.244 34.844 25.578 35.323 ;
     RECT  28.584 34.577 29.034 35.323 ;
     RECT  29.844 34.733 30.366 35.323 ;
     RECT  16.74 35.323 25.578 35.899 ;
     RECT  26.568 34.763 27.846 35.899 ;
     RECT  28.584 35.323 30.366 35.899 ;
     RECT  31.104 34.877 31.374 35.899 ;
     RECT  32.112 34.877 36.414 35.899 ;
     RECT  4.356 35.323 16.002 35.947 ;
     RECT  16.74 35.899 36.666 35.947 ;
     RECT  4.356 35.947 36.666 36.588 ;
     RECT  27.108 36.588 27.198 36.653 ;
     RECT  32.904 36.588 32.994 36.653 ;
    LAYER M4 ;
     RECT  2.408 2.148 2.512 34.572 ;
     RECT  2.512 2.418 2.704 34.302 ;
     RECT  4.46 34.8 4.597 34.824 ;
     RECT  2.704 3.408 4.981 3.432 ;
     RECT  4.597 34.8 5.027 35.352 ;
     RECT  4.481 1.728 5.108 1.752 ;
     RECT  4.981 2.88 5.108 3.432 ;
     RECT  4.705 4.656 5.108 4.68 ;
     RECT  5.027 34.8 5.108 34.824 ;
     RECT  5.108 1.728 5.321 34.824 ;
     RECT  5.321 1.728 5.404 34.344 ;
     RECT  5.404 1.728 5.501 2.904 ;
     RECT  5.404 4.416 5.537 4.68 ;
     RECT  5.404 5.664 5.581 6.264 ;
     RECT  5.537 4.656 5.681 4.68 ;
     RECT  5.501 1.728 5.795 2.328 ;
     RECT  5.708 35.904 5.795 35.928 ;
     RECT  5.581 5.664 6.185 6.024 ;
     RECT  5.795 1.728 6.275 2.28 ;
     RECT  5.404 31.872 6.275 34.344 ;
     RECT  5.404 7.392 6.509 7.944 ;
     RECT  6.185 5.712 6.613 6.024 ;
     RECT  5.404 30.576 6.709 30.6 ;
     RECT  6.275 31.872 6.709 34.248 ;
     RECT  6.275 1.728 6.833 1.848 ;
     RECT  6.613 5.712 7.261 6.84 ;
     RECT  6.509 7.92 7.285 7.944 ;
     RECT  5.404 9.072 7.285 9.096 ;
     RECT  6.833 1.728 7.337 1.752 ;
     RECT  7.285 7.92 7.429 9.096 ;
     RECT  6.709 30.576 7.477 34.248 ;
     RECT  7.237 2.88 7.525 2.904 ;
     RECT  7.525 2.88 7.669 2.952 ;
     RECT  7.669 2.88 7.808 3 ;
     RECT  7.261 5.328 7.808 6.84 ;
     RECT  7.429 7.92 7.808 9.912 ;
     RECT  7.477 30.576 7.808 34.728 ;
     RECT  7.669 0.192 7.811 0.216 ;
     RECT  7.808 2.148 7.811 34.728 ;
     RECT  7.811 2.148 8.104 34.68 ;
     RECT  8.005 0.288 8.243 0.312 ;
     RECT  8.104 31.68 8.387 34.68 ;
     RECT  8.104 2.148 8.525 3.432 ;
     RECT  8.525 2.148 8.533 2.904 ;
     RECT  8.533 1.728 8.849 2.904 ;
     RECT  8.387 31.68 8.885 34.392 ;
     RECT  8.104 7.392 9.001 7.416 ;
     RECT  8.849 1.728 9.059 2.28 ;
     RECT  9.241 3.936 9.325 3.96 ;
     RECT  8.104 8.496 9.425 8.52 ;
     RECT  8.104 6 9.877 6.264 ;
     RECT  8.104 9.888 9.973 9.912 ;
     RECT  8.885 31.776 10.021 34.392 ;
     RECT  9.877 6 10.213 6.744 ;
     RECT  9.059 1.728 10.252 1.752 ;
     RECT  8.104 30.24 10.261 30.648 ;
     RECT  10.021 31.68 10.261 34.392 ;
     RECT  10.252 1.728 10.357 1.8 ;
     RECT  10.021 2.88 10.357 2.904 ;
     RECT  10.213 6 10.501 6.84 ;
     RECT  10.357 1.728 10.508 3.528 ;
     RECT  10.501 5.472 10.508 6.84 ;
     RECT  9.493 7.92 10.508 7.992 ;
     RECT  9.973 9.072 10.508 9.912 ;
     RECT  10.261 30.24 10.508 34.728 ;
     RECT  10.508 1.728 10.612 34.728 ;
     RECT  10.612 1.728 10.804 34.302 ;
     RECT  10.357 35.904 11.029 35.928 ;
     RECT  10.804 29.616 11.045 34.296 ;
     RECT  10.804 5.472 11.081 6.84 ;
     RECT  10.804 1.728 11.377 1.8 ;
     RECT  11.045 30.768 11.585 34.296 ;
     RECT  10.804 7.92 11.801 7.944 ;
     RECT  11.045 29.616 11.845 29.64 ;
     RECT  10.804 3.936 11.909 4.392 ;
     RECT  10.804 9.072 11.945 9.912 ;
     RECT  11.945 9.264 11.981 9.912 ;
     RECT  11.845 29.088 11.987 29.64 ;
     RECT  11.029 35.328 12.035 35.928 ;
     RECT  11.585 31.536 12.161 34.296 ;
     RECT  11.909 4.224 12.553 4.392 ;
     RECT  11.797 2.88 13.093 2.904 ;
     RECT  12.553 4.224 13.093 4.776 ;
     RECT  12.035 35.904 13.139 35.928 ;
     RECT  11.377 1.728 13.208 1.752 ;
     RECT  13.093 2.88 13.208 4.776 ;
     RECT  11.081 6.24 13.208 6.84 ;
     RECT  12.853 7.968 13.208 7.992 ;
     RECT  11.981 9.264 13.208 9.288 ;
     RECT  12.133 12.528 13.208 12.552 ;
     RECT  12.901 26.208 13.208 26.232 ;
     RECT  12.689 28.464 13.208 28.488 ;
     RECT  11.987 29.616 13.208 29.64 ;
     RECT  12.161 31.536 13.208 34.104 ;
     RECT  13.208 1.728 13.333 34.572 ;
     RECT  13.333 0.288 13.477 0.312 ;
     RECT  13.333 1.728 13.504 34.728 ;
     RECT  13.477 0.192 13.619 0.312 ;
     RECT  13.504 3.024 13.619 4.248 ;
     RECT  13.504 31.68 13.667 34.728 ;
     RECT  13.667 31.68 13.673 34.488 ;
     RECT  13.673 31.92 13.709 34.488 ;
     RECT  13.709 31.92 13.817 34.248 ;
     RECT  13.619 3.408 14.099 4.248 ;
     RECT  13.504 9.264 14.357 9.288 ;
     RECT  13.504 5.664 14.533 7.416 ;
     RECT  14.485 28.464 14.681 28.488 ;
     RECT  14.533 5.664 14.861 7.992 ;
     RECT  13.817 31.92 15.013 34.104 ;
     RECT  14.099 3.936 15.061 4.248 ;
     RECT  13.504 1.728 15.077 1.752 ;
     RECT  14.713 35.904 15.469 35.928 ;
     RECT  15.013 31.824 15.505 34.104 ;
     RECT  15.469 35.328 15.553 35.928 ;
     RECT  15.061 3.216 15.589 4.248 ;
     RECT  15.505 31.824 15.637 34.248 ;
     RECT  15.733 0.192 15.875 0.216 ;
     RECT  15.325 1.776 15.908 1.8 ;
     RECT  15.589 2.88 15.908 4.248 ;
     RECT  14.861 5.904 15.908 7.992 ;
     RECT  15.685 11.232 15.908 11.256 ;
     RECT  15.637 31.824 15.908 34.728 ;
     RECT  15.908 1.776 16.069 34.728 ;
     RECT  16.069 1.728 16.204 34.728 ;
     RECT  15.553 35.904 16.225 35.928 ;
     RECT  16.204 5.952 16.355 7.416 ;
     RECT  16.225 35.904 16.357 35.976 ;
     RECT  16.204 8.448 16.403 9.096 ;
     RECT  16.204 30.192 16.451 34.728 ;
     RECT  16.357 35.904 16.477 36.024 ;
     RECT  16.355 6.24 16.489 6.84 ;
     RECT  16.451 30.768 16.499 34.728 ;
     RECT  16.477 35.904 16.729 36.072 ;
     RECT  16.204 17.616 16.841 17.64 ;
     RECT  16.204 1.728 17.017 1.752 ;
     RECT  16.729 35.328 17.036 36.072 ;
     RECT  17.036 35.328 17.157 36.504 ;
     RECT  16.204 2.88 17.165 3.96 ;
     RECT  17.157 35.328 17.171 35.928 ;
     RECT  16.499 30.768 17.209 34.248 ;
     RECT  17.017 1.152 17.219 1.752 ;
     RECT  17.171 35.328 17.345 35.352 ;
     RECT  17.209 31.536 17.605 34.248 ;
     RECT  16.403 9.072 17.633 9.096 ;
     RECT  17.219 1.728 17.669 1.752 ;
     RECT  16.489 6.336 17.873 6.84 ;
     RECT  17.593 7.968 17.873 7.992 ;
     RECT  17.873 6.336 17.909 7.992 ;
     RECT  17.909 6.24 18.061 7.992 ;
     RECT  17.605 31.536 18.229 34.344 ;
     RECT  17.165 2.88 18.413 2.904 ;
     RECT  18.061 5.328 18.421 7.992 ;
     RECT  18.413 2.784 18.469 2.904 ;
     RECT  17.165 3.936 18.469 3.96 ;
     RECT  18.469 2.784 18.608 3.96 ;
     RECT  18.421 5.184 18.608 7.992 ;
     RECT  16.204 29.088 18.608 29.112 ;
     RECT  18.229 31.536 18.608 34.728 ;
     RECT  18.469 0.192 18.659 0.216 ;
     RECT  18.241 35.904 18.745 35.928 ;
     RECT  18.608 2.148 18.853 34.728 ;
     RECT  18.853 1.68 18.904 34.728 ;
     RECT  18.904 1.68 18.965 1.752 ;
     RECT  18.745 35.904 19.043 35.976 ;
     RECT  18.965 1.728 19.289 1.752 ;
     RECT  18.904 31.536 19.433 34.728 ;
     RECT  19.043 35.904 19.475 35.928 ;
     RECT  19.501 35.328 19.585 35.4 ;
     RECT  18.904 6 19.657 6.84 ;
     RECT  18.904 2.88 19.693 3.96 ;
     RECT  18.904 10.8 19.715 10.824 ;
     RECT  19.657 6.048 20.005 6.84 ;
     RECT  20.005 6.048 20.089 7.416 ;
     RECT  19.693 3.408 20.293 3.96 ;
     RECT  20.293 3.408 20.297 4.728 ;
     RECT  18.904 9.648 20.501 9.672 ;
     RECT  19.585 35.376 20.629 35.4 ;
     RECT  20.297 4.704 20.677 4.728 ;
     RECT  20.089 6.048 20.677 6.84 ;
     RECT  20.297 3.408 20.869 3.432 ;
     RECT  20.389 1.728 21.109 1.752 ;
     RECT  20.869 2.88 21.109 3.432 ;
     RECT  20.629 35.328 21.155 35.4 ;
     RECT  19.433 31.536 21.157 34.248 ;
     RECT  21.109 1.728 21.265 3.432 ;
     RECT  20.677 4.704 21.265 6.84 ;
     RECT  21.265 1.728 21.308 6.84 ;
     RECT  20.501 9.648 21.308 10.248 ;
     RECT  21.109 18.192 21.308 18.216 ;
     RECT  21.157 31.536 21.308 34.68 ;
     RECT  21.308 1.728 21.604 34.68 ;
     RECT  21.604 18.192 21.701 18.216 ;
     RECT  21.604 31.824 21.724 34.68 ;
     RECT  21.397 35.904 21.725 35.928 ;
     RECT  21.724 31.824 21.745 34.584 ;
     RECT  21.725 35.904 21.809 35.976 ;
     RECT  21.745 31.824 21.827 34.392 ;
     RECT  21.604 9.072 21.853 9.096 ;
     RECT  21.604 3.408 22.025 6.84 ;
     RECT  21.604 29.088 22.211 29.112 ;
     RECT  21.604 10.224 22.277 10.248 ;
     RECT  21.827 31.824 22.645 33.672 ;
     RECT  22.025 6 22.681 6.84 ;
     RECT  22.025 3.408 22.781 4.824 ;
     RECT  22.645 31.776 22.837 33.672 ;
     RECT  22.837 31.776 22.885 33.72 ;
     RECT  22.885 31.536 22.933 33.72 ;
     RECT  21.809 35.904 23.321 35.928 ;
     RECT  22.781 3.984 23.353 4.824 ;
     RECT  22.681 6 23.353 6.6 ;
     RECT  22.933 31.536 23.489 34.248 ;
     RECT  21.604 1.728 23.537 1.752 ;
     RECT  23.365 9.072 23.605 9.096 ;
     RECT  23.125 2.88 23.653 2.904 ;
     RECT  23.605 8.832 23.797 9.096 ;
     RECT  23.653 2.148 24.008 2.904 ;
     RECT  23.353 3.984 24.008 6.6 ;
     RECT  23.797 8.832 24.008 9.624 ;
     RECT  22.957 26.784 24.008 26.808 ;
     RECT  23.489 31.536 24.008 34.296 ;
     RECT  24.008 2.148 24.037 34.572 ;
     RECT  21.205 0.192 24.133 0.216 ;
     RECT  24.037 2.148 24.304 35.352 ;
     RECT  24.133 0.192 24.419 0.312 ;
     RECT  24.304 2.88 24.419 3.912 ;
     RECT  24.304 31.536 24.419 35.352 ;
     RECT  24.419 31.536 24.515 34.728 ;
     RECT  24.304 9.6 24.545 10.248 ;
     RECT  24.515 31.536 24.556 34.248 ;
     RECT  24.304 5.04 24.725 5.064 ;
     RECT  24.304 6.096 24.985 6.84 ;
     RECT  24.545 10.224 25.733 10.248 ;
     RECT  24.661 1.728 25.765 1.752 ;
     RECT  24.419 3.888 25.765 3.912 ;
     RECT  24.556 31.872 25.909 34.248 ;
     RECT  25.717 13.632 26.005 13.656 ;
     RECT  24.985 6.096 26.293 6.6 ;
     RECT  24.793 35.904 26.305 35.928 ;
     RECT  25.909 31.872 26.389 34.824 ;
     RECT  25.765 3.888 26.485 4.008 ;
     RECT  25.765 1.728 26.708 1.8 ;
     RECT  24.419 2.88 26.708 2.904 ;
     RECT  26.485 3.888 26.708 4.536 ;
     RECT  26.293 6.096 26.708 6.84 ;
     RECT  26.005 12.768 26.708 13.656 ;
     RECT  26.389 31.872 26.708 34.872 ;
     RECT  24.419 0.192 26.917 0.216 ;
     RECT  26.708 1.728 27.004 34.872 ;
     RECT  26.917 0.192 27.245 0.312 ;
     RECT  27.004 5.712 27.347 8.184 ;
     RECT  26.305 35.904 27.443 35.976 ;
     RECT  27.004 31.296 27.971 34.872 ;
     RECT  27.971 31.344 28.217 34.872 ;
     RECT  27.004 12.768 28.325 12.792 ;
     RECT  27.347 5.712 28.393 7.368 ;
     RECT  27.004 2.88 28.421 2.952 ;
     RECT  28.393 5.136 28.429 7.368 ;
     RECT  28.421 2.88 28.504 3.432 ;
     RECT  28.429 4.656 28.709 7.368 ;
     RECT  28.465 10.608 29.077 10.632 ;
     RECT  27.443 35.904 29.077 35.928 ;
     RECT  27.004 1.728 29.221 1.752 ;
     RECT  28.504 2.88 29.221 3.48 ;
     RECT  29.221 1.728 29.257 3.48 ;
     RECT  28.709 4.656 29.257 7.416 ;
     RECT  27.245 0.288 29.269 0.312 ;
     RECT  28.217 31.824 29.269 34.872 ;
     RECT  29.077 35.904 29.269 35.976 ;
     RECT  29.269 31.824 29.369 35.976 ;
     RECT  29.257 1.728 29.408 7.416 ;
     RECT  29.077 9.888 29.408 10.632 ;
     RECT  28.177 30.336 29.408 30.36 ;
     RECT  29.369 31.824 29.408 34.872 ;
     RECT  29.369 35.904 29.461 35.976 ;
     RECT  29.461 35.904 29.581 36.024 ;
     RECT  29.408 1.728 29.704 34.872 ;
     RECT  29.704 2.88 29.765 4.152 ;
     RECT  29.704 9.888 29.801 10.872 ;
     RECT  29.704 30.336 30.083 34.872 ;
     RECT  29.581 35.904 30.085 36.12 ;
     RECT  29.801 10.032 30.757 10.872 ;
     RECT  29.269 0.192 30.809 0.312 ;
     RECT  30.757 10.032 30.809 10.92 ;
     RECT  29.704 6.096 30.899 7.368 ;
     RECT  30.809 10.128 30.899 10.92 ;
     RECT  30.757 14.688 30.899 14.856 ;
     RECT  30.757 18.768 30.899 18.936 ;
     RECT  30.757 22.608 30.899 22.92 ;
     RECT  30.757 26.64 30.899 26.952 ;
     RECT  30.899 14.784 30.995 14.856 ;
     RECT  30.899 18.768 30.995 18.84 ;
     RECT  30.899 22.704 30.995 22.824 ;
     RECT  30.899 26.736 30.995 26.856 ;
     RECT  30.899 10.128 31.091 10.872 ;
     RECT  30.995 14.784 31.091 14.808 ;
     RECT  30.995 18.816 31.091 18.84 ;
     RECT  30.995 22.704 31.091 22.728 ;
     RECT  29.704 1.728 31.477 1.8 ;
     RECT  30.899 6.096 31.741 7.128 ;
     RECT  30.083 30.336 32.005 34.824 ;
     RECT  32.005 30.336 32.092 34.872 ;
     RECT  31.477 1.728 32.108 1.848 ;
     RECT  29.765 2.88 32.108 3.864 ;
     RECT  31.741 5.472 32.108 7.128 ;
     RECT  29.704 8.784 32.108 8.808 ;
     RECT  31.091 10.128 32.108 10.632 ;
     RECT  31.669 12.768 32.108 12.792 ;
     RECT  32.092 30.336 32.108 34.824 ;
     RECT  32.108 1.728 32.404 34.824 ;
     RECT  30.809 0.288 32.453 0.312 ;
     RECT  32.404 1.728 32.453 3.864 ;
     RECT  32.453 0.288 32.465 3.864 ;
     RECT  32.465 0.288 32.537 1.752 ;
     RECT  32.404 10.128 32.579 10.632 ;
     RECT  32.537 1.728 32.771 1.752 ;
     RECT  32.465 2.832 32.915 3.864 ;
     RECT  32.404 5.088 32.956 7.416 ;
     RECT  32.915 2.88 33.299 3.864 ;
     RECT  32.956 5.472 33.337 7.416 ;
     RECT  30.085 35.904 33.443 36.504 ;
     RECT  33.299 3.648 33.461 3.864 ;
     RECT  32.404 8.784 33.757 8.808 ;
     RECT  33.337 5.472 33.761 7.128 ;
     RECT  32.404 12.768 33.937 12.792 ;
     RECT  33.733 1.728 33.965 1.752 ;
     RECT  32.404 31.104 34.069 34.824 ;
     RECT  33.443 35.904 34.069 36.072 ;
     RECT  33.757 8.784 34.153 9.48 ;
     RECT  32.579 10.608 34.153 10.632 ;
     RECT  34.069 31.104 34.157 36.072 ;
     RECT  33.461 3.648 34.364 4.008 ;
     RECT  34.157 35.952 34.403 36.072 ;
     RECT  34.153 8.784 34.441 10.632 ;
     RECT  34.157 31.104 34.441 34.872 ;
     RECT  34.364 3.648 34.613 4.296 ;
     RECT  32.537 0.288 34.645 0.312 ;
     RECT  34.613 2.88 34.657 4.296 ;
     RECT  34.645 0.192 34.787 0.312 ;
     RECT  33.965 1.728 34.808 1.848 ;
     RECT  34.657 2.88 34.808 4.776 ;
     RECT  33.761 6.096 34.808 7.128 ;
     RECT  34.441 8.784 34.808 11.448 ;
     RECT  33.937 12.768 34.808 12.84 ;
     RECT  34.441 30.576 34.808 34.872 ;
     RECT  34.808 1.728 35.104 34.872 ;
     RECT  35.104 10.128 35.219 11.448 ;
     RECT  35.104 30.576 35.267 34.872 ;
     RECT  35.104 1.728 35.345 4.776 ;
     RECT  35.345 3.648 35.597 4.776 ;
     RECT  34.403 35.952 35.603 35.976 ;
     RECT  35.267 30.576 35.641 34.824 ;
     RECT  35.641 32.16 35.651 34.824 ;
     RECT  35.641 30.576 35.939 31.176 ;
     RECT  35.345 1.728 36.035 2.328 ;
     RECT  35.651 32.448 36.065 34.824 ;
     RECT  35.104 6.192 36.097 8.808 ;
     RECT  35.939 30.576 36.241 31.128 ;
     RECT  36.065 32.496 36.275 34.824 ;
     RECT  36.035 1.728 36.353 2.28 ;
     RECT  36.241 29.664 36.515 31.128 ;
     RECT  35.597 3.648 36.601 4.104 ;
     RECT  34.787 0.288 36.677 0.312 ;
     RECT  36.565 35.904 36.677 35.928 ;
     RECT  36.601 3.36 37.033 4.104 ;
     RECT  36.097 5.472 37.033 8.808 ;
     RECT  36.275 32.688 37.465 34.824 ;
     RECT  36.353 2.256 37.508 2.28 ;
     RECT  37.033 3.36 37.508 8.808 ;
     RECT  35.219 10.128 37.508 10.632 ;
     RECT  35.104 12.768 37.508 12.84 ;
     RECT  36.515 29.664 37.508 30.792 ;
     RECT  37.465 32.256 37.508 34.824 ;
     RECT  37.508 2.148 37.612 34.824 ;
     RECT  37.612 2.256 37.649 34.824 ;
     RECT  37.649 2.418 37.804 34.824 ;
     RECT  37.804 32.256 38.003 34.824 ;
     RECT  37.804 2.784 38.339 3.96 ;
     RECT  38.003 32.544 38.435 34.824 ;
     RECT  38.339 3.408 38.441 3.96 ;
     RECT  38.441 3.408 38.485 3.432 ;
     RECT  38.435 32.544 38.675 32.568 ;
     RECT  37.804 5.664 38.701 6.6 ;
     RECT  37.804 12.768 38.773 12.84 ;
     RECT  38.773 12.768 38.819 12.936 ;
     RECT  37.804 30.576 38.819 30.6 ;
     RECT  37.804 10.128 38.867 10.632 ;
     RECT  38.435 33.648 38.867 34.824 ;
     RECT  38.867 10.608 38.915 10.632 ;
     RECT  38.819 12.816 38.963 12.936 ;
     RECT  38.867 33.648 38.963 34.44 ;
     RECT  38.963 12.912 39.011 12.936 ;
     RECT  38.963 33.648 39.011 34.392 ;
     RECT  38.701 6.576 39.059 6.6 ;
     RECT  39.011 34.368 39.059 34.392 ;
    LAYER M5 ;
     RECT  4.512 0.144 36.552 1.763 ;
     RECT  10.032 1.763 14.088 1.811 ;
     RECT  4.992 1.763 9.048 1.859 ;
     RECT  25.44 1.763 36.552 1.859 ;
     RECT  34.656 1.859 36.552 2.137 ;
     RECT  2.4 2.137 2.52 2.151 ;
     RECT  34.656 2.137 37.62 2.151 ;
     RECT  4.992 1.859 6.264 2.291 ;
     RECT  7.248 1.859 9.048 2.291 ;
     RECT  34.656 2.151 37.812 2.291 ;
     RECT  4.992 2.291 5.784 2.339 ;
     RECT  34.656 2.291 36.024 2.339 ;
     RECT  37.5 2.291 37.812 2.773 ;
     RECT  4.992 2.339 5.412 2.915 ;
     RECT  7.248 2.291 8.808 2.915 ;
     RECT  10.032 1.811 10.812 2.915 ;
     RECT  11.808 1.811 14.088 2.915 ;
     RECT  17.856 1.763 24.456 2.915 ;
     RECT  25.44 1.859 30.984 2.915 ;
     RECT  34.656 2.339 35.304 2.915 ;
     RECT  7.536 2.915 8.232 2.963 ;
     RECT  26.7 2.915 27.48 2.963 ;
     RECT  7.68 2.963 8.232 3.011 ;
     RECT  31.968 1.859 33.528 3.059 ;
     RECT  15.072 1.763 16.872 3.251 ;
     RECT  15.36 3.251 16.872 3.347 ;
     RECT  37.5 2.773 38.328 3.397 ;
     RECT  7.8 3.011 8.232 3.443 ;
     RECT  13.104 2.915 14.088 3.443 ;
     RECT  15.36 3.347 16.392 3.443 ;
     RECT  18.432 2.915 20.136 3.443 ;
     RECT  21.12 2.915 22.68 3.443 ;
     RECT  24 2.915 24.408 3.443 ;
     RECT  28.464 2.915 29.832 3.443 ;
     RECT  28.56 3.443 29.712 3.491 ;
     RECT  10.368 2.915 10.812 3.539 ;
     RECT  13.104 3.443 13.512 3.923 ;
     RECT  10.5 3.539 10.812 3.925 ;
     RECT  32.1 3.059 33.528 4.019 ;
     RECT  34.8 2.915 35.112 4.261 ;
     RECT  26.7 2.963 27.012 4.501 ;
     RECT  29.4 3.491 29.712 5.077 ;
     RECT  32.1 4.019 32.904 5.123 ;
     RECT  18.432 3.443 18.912 5.219 ;
     RECT  21.12 3.443 21.612 5.317 ;
     RECT  5.1 2.915 5.412 5.653 ;
     RECT  37.5 3.397 38.472 5.653 ;
     RECT  5.1 5.653 6.168 5.701 ;
     RECT  18.6 5.219 18.912 5.989 ;
     RECT  37.344 5.653 38.664 5.989 ;
     RECT  7.8 3.443 8.112 6.085 ;
     RECT  20.688 5.317 21.612 6.085 ;
     RECT  22.8 5.989 22.824 6.085 ;
     RECT  20.688 6.085 22.824 6.181 ;
     RECT  34.416 4.261 35.112 6.181 ;
     RECT  36.72 5.989 38.664 6.181 ;
     RECT  5.1 5.701 6.696 6.229 ;
     RECT  7.68 6.085 8.112 6.229 ;
     RECT  9.264 3.925 9.288 6.229 ;
     RECT  10.5 3.925 11.736 6.229 ;
     RECT  13.2 3.923 13.512 6.229 ;
     RECT  15.36 3.443 16.344 6.229 ;
     RECT  18.6 5.989 19.608 6.229 ;
     RECT  20.688 6.181 22.968 6.229 ;
     RECT  24 3.443 24.312 6.229 ;
     RECT  32.1 5.123 32.412 6.229 ;
     RECT  34.416 6.181 38.664 6.229 ;
     RECT  26.496 4.501 27.012 6.469 ;
     RECT  34.128 6.229 38.664 6.565 ;
     RECT  5.1 6.229 16.44 6.757 ;
     RECT  17.952 6.229 22.968 6.757 ;
     RECT  29.28 5.077 29.712 6.757 ;
     RECT  30.816 6.181 30.84 6.757 ;
     RECT  32.1 6.229 33.144 6.757 ;
     RECT  26.496 6.469 27.816 6.805 ;
     RECT  30.816 6.757 33.144 6.805 ;
     RECT  34.128 6.565 39.048 6.805 ;
     RECT  26.304 6.805 27.816 7.381 ;
     RECT  28.848 6.757 29.712 7.381 ;
     RECT  5.1 6.757 22.968 8.821 ;
     RECT  24 6.229 25.224 8.821 ;
     RECT  30.816 6.805 39.048 10.741 ;
     RECT  30.768 10.741 39.048 10.931 ;
     RECT  5.1 8.821 25.224 12.757 ;
     RECT  26.304 7.381 29.712 12.757 ;
     RECT  30.816 10.931 39.048 14.677 ;
     RECT  30.768 14.677 39.048 14.867 ;
     RECT  30.816 14.867 39.048 18.757 ;
     RECT  30.768 18.757 39.048 18.947 ;
     RECT  30.816 18.947 39.048 22.597 ;
     RECT  30.768 22.597 39.048 22.931 ;
     RECT  30.816 22.931 39.048 26.629 ;
     RECT  30.768 26.629 39.048 26.963 ;
     RECT  30.816 26.963 39.048 30.709 ;
     RECT  5.1 12.757 29.712 31.669 ;
     RECT  30.768 30.709 39.048 31.669 ;
     RECT  5.1 31.669 39.048 34.163 ;
     RECT  38.784 34.163 39.048 34.211 ;
     RECT  38.832 34.211 39.048 34.403 ;
     RECT  38.832 34.403 38.952 34.451 ;
     RECT  2.4 2.151 2.712 34.569 ;
     RECT  5.1 34.163 37.812 34.569 ;
     RECT  2.4 34.569 2.52 34.583 ;
     RECT  5.1 34.569 37.62 34.583 ;
     RECT  5.1 34.583 36.6 34.789 ;
     RECT  38.832 34.451 38.856 34.835 ;
     RECT  4.512 34.789 36.6 35.939 ;
     RECT  4.512 35.939 36.552 36.56 ;
     RECT  9.048 1.763 10.032 2.291 ;
     RECT  14.088 1.763 15.072 3.251 ;
     RECT  16.872 1.763 17.856 2.915 ;
     RECT  24.456 1.763 25.44 2.915 ;
     RECT  10.812 1.811 11.808 2.915 ;
     RECT  6.264 1.859 7.248 2.291 ;
     RECT  30.984 1.859 31.968 2.915 ;
     RECT  33.528 1.859 34.656 2.915 ;
     RECT  5.784 2.291 7.248 2.339 ;
     RECT  8.808 2.291 10.032 2.915 ;
     RECT  36.024 2.291 37.5 2.339 ;
     RECT  8.232 2.915 10.368 3.443 ;
     RECT  10.812 2.915 13.104 3.923 ;
     RECT  20.136 2.915 21.12 3.443 ;
     RECT  22.68 2.915 24 3.443 ;
     RECT  27.48 2.915 28.464 2.963 ;
     RECT  33.528 2.915 34.8 4.019 ;
     RECT  27.012 2.963 28.464 3.443 ;
     RECT  14.088 3.251 15.36 3.443 ;
     RECT  8.112 3.443 10.368 3.539 ;
     RECT  8.112 3.539 10.5 3.925 ;
     RECT  10.812 3.923 13.2 3.925 ;
     RECT  8.112 3.925 9.264 6.229 ;
     RECT  9.288 3.925 10.5 6.229 ;
     RECT  11.736 3.925 13.2 6.229 ;
     RECT  32.904 4.019 34.8 4.261 ;
     RECT  32.904 4.261 34.416 5.123 ;
     RECT  32.412 5.123 34.416 6.229 ;
     RECT  18.432 5.219 18.6 6.229 ;
     RECT  6.696 5.701 7.8 6.085 ;
     RECT  19.608 5.989 20.688 6.229 ;
     RECT  21.612 5.989 22.8 6.085 ;
     RECT  22.824 5.989 24 6.181 ;
     RECT  6.696 6.085 7.68 6.229 ;
     RECT  22.968 6.181 24 8.821 ;
     RECT  29.712 6.181 30.816 10.741 ;
     RECT  30.84 6.181 32.1 6.757 ;
     RECT  16.44 6.229 17.952 6.757 ;
     RECT  25.224 6.229 26.496 6.805 ;
     RECT  33.144 6.229 34.128 6.805 ;
     RECT  27.816 6.469 29.28 6.757 ;
     RECT  27.816 6.757 28.848 7.381 ;
     RECT  25.224 6.805 26.304 12.757 ;
     RECT  29.712 10.741 30.768 10.931 ;
     RECT  29.712 10.931 30.816 14.677 ;
     RECT  29.712 14.677 30.768 14.867 ;
     RECT  29.712 14.867 30.816 18.757 ;
     RECT  29.712 18.757 30.768 18.947 ;
     RECT  29.712 18.947 30.816 22.597 ;
     RECT  29.712 22.597 30.768 22.931 ;
     RECT  29.712 22.931 30.816 26.629 ;
     RECT  29.712 26.629 30.768 26.963 ;
     RECT  29.712 26.963 30.816 30.709 ;
     RECT  29.712 30.709 30.768 31.669 ;
     RECT  37.812 34.163 38.784 34.211 ;
     RECT  37.812 34.211 38.832 34.569 ;
     RECT  37.62 34.569 38.832 34.583 ;
  END
END dsfd_stnv_256x1
END LIBRARY
